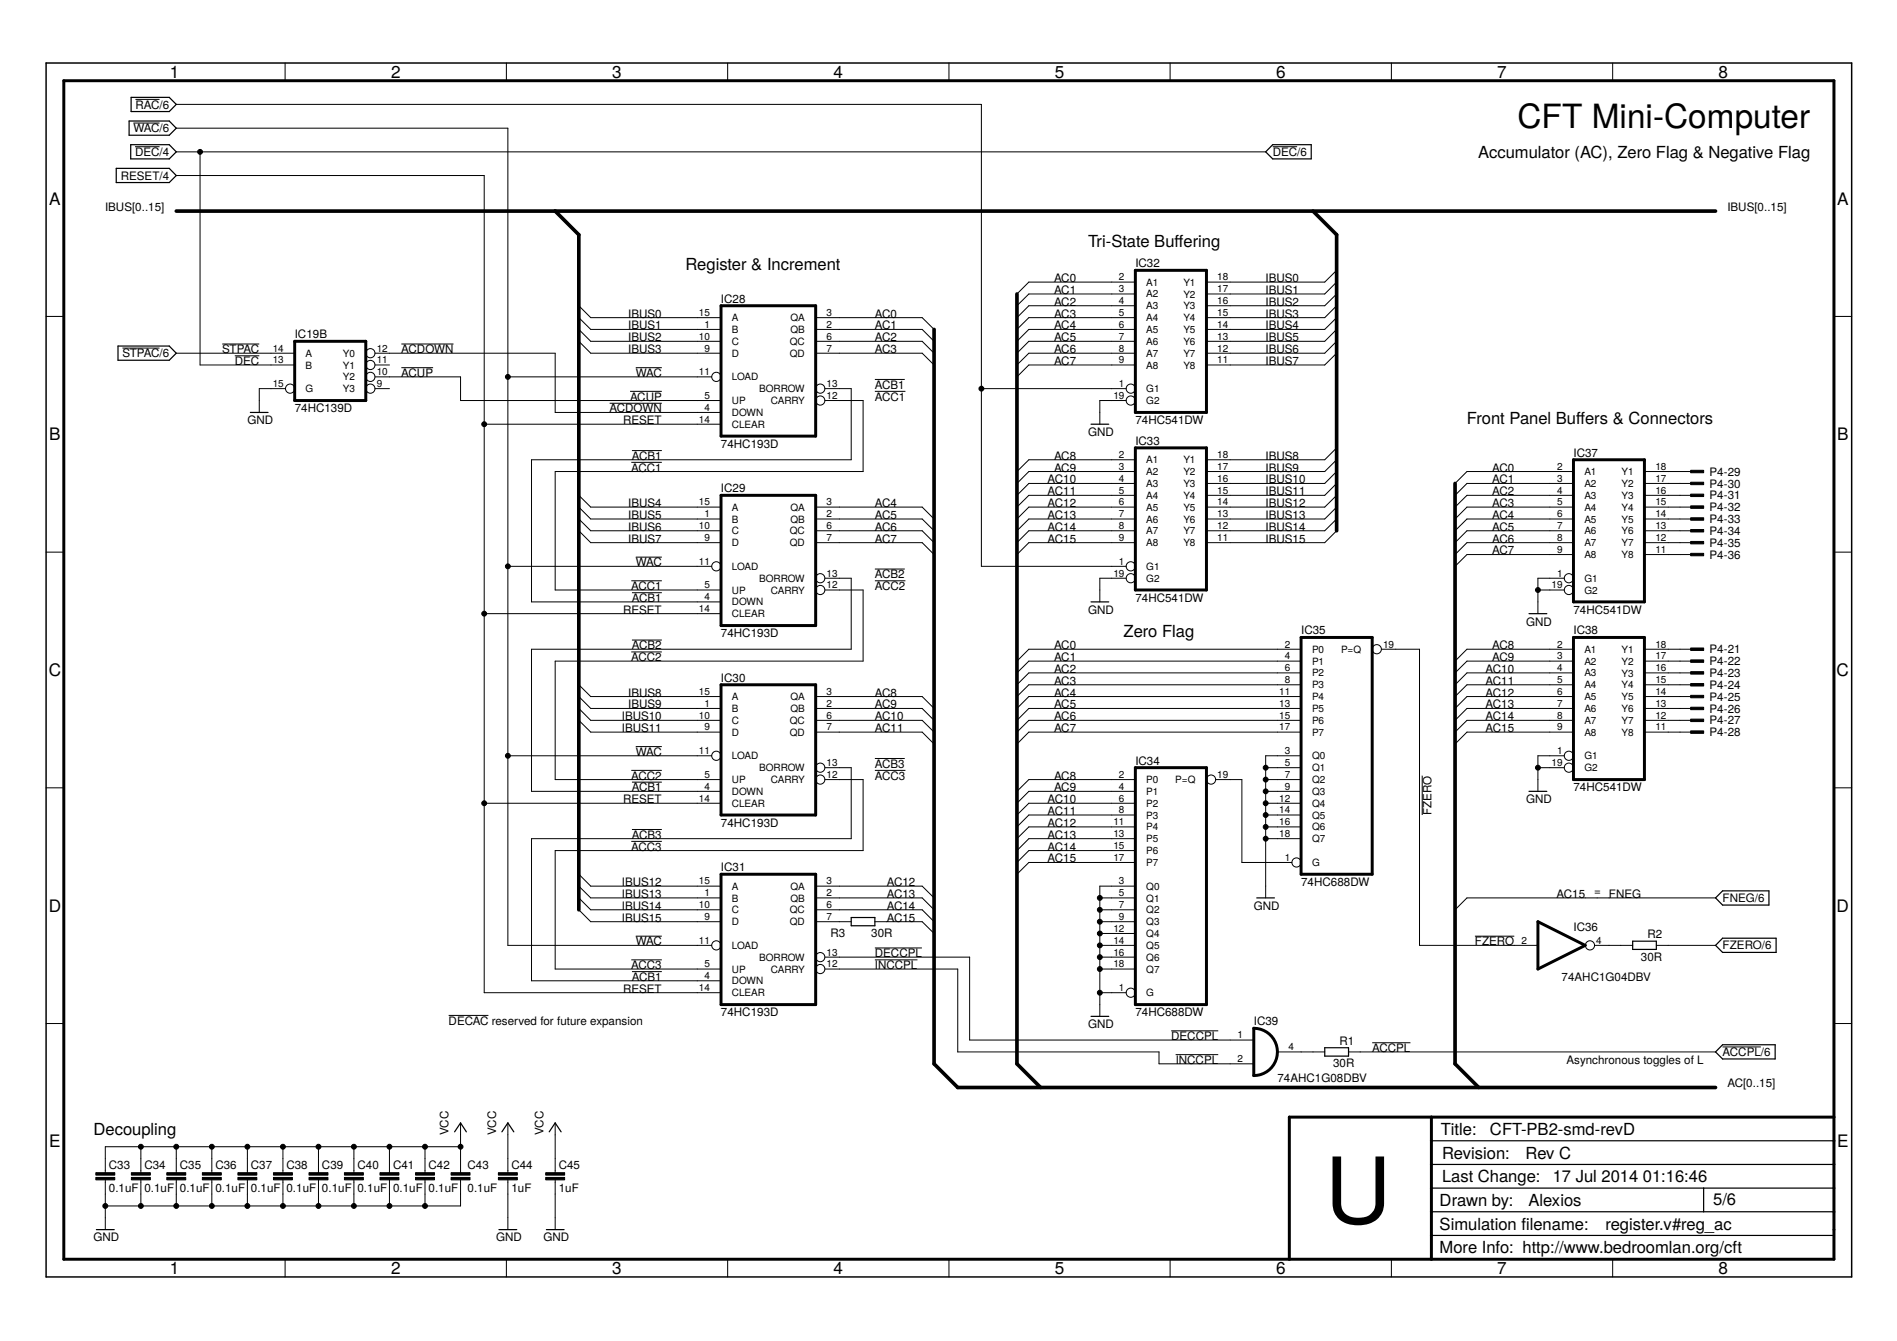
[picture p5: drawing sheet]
<svg xmlns="http://www.w3.org/2000/svg" width="297mm" height="210mm" viewBox="0 0 297 210" stroke-linecap="round" stroke-linejoin="round" font-family="sans-serif">
<defs><g id="words">
<text font-size="14.4" x="207.4" y="191.5">U</text>
<text font-size="5.2" x="237.6" y="20.1">CFT Mini-Computer</text>
<g font-size="2.7">
<text x="26.6" y="12.2">1</text>
<text x="61.2" y="12.2">2</text>
<text x="95.9" y="12.2">3</text>
<text x="130.5" y="12.2">4</text>
<text x="165.2" y="12.2">5</text>
<text x="199.8" y="12.2">6</text>
<text x="234.5" y="12.2">7</text>
<text x="269.1" y="12.2">8</text>
<text x="7.7" y="32">A</text>
<text x="287.7" y="32">A</text>
<text x="7.7" y="68.9">B</text>
<text x="287.7" y="68.9">B</text>
<text x="7.6" y="105.8">C</text>
<text x="287.6" y="105.8">C</text>
<text x="7.6" y="142.7">D</text>
<text x="287.6" y="142.7">D</text>
<text x="7.7" y="179.6">E</text>
<text x="287.7" y="179.6">E</text>
<text x="26.6" y="199.4">1</text>
<text x="61.2" y="199.4">2</text>
<text x="95.9" y="199.4">3</text>
<text x="130.5" y="199.4">4</text>
<text x="165.2" y="199.4">5</text>
<text x="199.8" y="199.4">6</text>
<text x="234.5" y="199.4">7</text>
<text x="269.1" y="199.4">8</text>
</g>
<g font-size="2.6">
<text x="231.4" y="24.7">Accumulator (AC), Zero Flag &amp; Negative Flag</text>
<text x="170.4" y="38.6">Tri-State Bufering</text>
<text x="183.9" y="38.6">f</text>
<text x="107.3" y="42.3">Register &amp; Increment</text>
<text x="229.7" y="66.4">Front Panel Bufers &amp; Connectors</text>
<text x="246.8" y="66.4">f</text>
<text x="175.9" y="99.8">Zero Flag</text>
<text x="14.6" y="177.6">Decoupling</text>
<text x="225.6" y="177.6">Title:</text>
<text x="233.3" y="177.7">CFT-PB2-smd-revD</text>
<text x="225.8" y="181.3">Revision:</text>
<text x="225.8" y="185">Last Change:</text>
<text x="238.9" y="181.4">Rev C</text>
<text x="243.1" y="185">17 Jul 2014</text>
<text x="257.3" y="185">01:16:46</text>
<text x="225.4" y="188.8">Drawn by:</text>
<text x="239.3" y="188.8">Alexios</text>
<text x="268.3" y="188.7">5/6</text>
<text x="225.4" y="192.5">Simulation flename:</text>
<text x="225.4" y="196.2">More Info: http://www.bedroomlan.org/cft</text>
<text x="238.2" y="192.5">i</text>
<text x="251.4" y="192.5">register.v#reg_ac</text>
</g>
<g font-size="1.8">
<text x="21.2" y="17">RAC/6</text>
<text x="20.9" y="20.7">WAC/6</text>
<text x="18.9" y="28.1">RESET/4</text>
<text x="21.1" y="24.4">DEC/4</text>
<text x="199.3" y="24.4">DEC/6</text>
<text x="16.4" y="33">IBUS[0..15]</text>
<text x="270.5" y="33">IBUS[0..15]</text>
<text x="177.8" y="41.8">IC32</text>
<text x="112.9" y="47.4">IC28</text>
<text x="165" y="44.2">AC0</text>
<text x="165" y="46">AC1</text>
<text x="165" y="47.9">AC2</text>
<text x="198.2" y="44.2">IBUS0</text>
<text x="198.2" y="46">IBUS1</text>
<text x="198.2" y="47.9">IBUS2</text>
<text x="46.2" y="53">IC19B</text>
<text x="98.4" y="49.7">IBUS0</text>
<text x="98.4" y="51.6">IBUS1</text>
<text x="98.4" y="53.4">IBUS2</text>
<text x="137" y="49.7">AC0</text>
<text x="137" y="51.6">AC1</text>
<text x="137" y="53.4">AC2</text>
<text x="165" y="49.7">AC3</text>
<text x="165" y="51.6">AC4</text>
<text x="165" y="53.4">AC5</text>
<text x="198.2" y="49.7">IBUS3</text>
<text x="198.2" y="51.6">IBUS4</text>
<text x="198.2" y="53.4">IBUS5</text>
<text x="19.2" y="55.9">STPAC/6</text>
<text x="34.8" y="55.3">STPAC</text>
<text x="36.8" y="57.1">DEC</text>
<text x="62.8" y="55.3">ACDOWN</text>
<text x="62.8" y="59">ACUP</text>
<text x="98.4" y="55.3">IBUS3</text>
<text x="99.5" y="59">WAC</text>
<text x="137" y="55.3">AC3</text>
<text x="165" y="55.3">AC6</text>
<text x="165" y="57.1">AC7</text>
<text x="198.2" y="55.3">IBUS6</text>
<text x="198.2" y="57.1">IBUS7</text>
<text x="46.2" y="64.5">74HC139D</text>
<text x="95.5" y="64.5">ACDOWN</text>
<text x="98.6" y="62.7">ACUP</text>
<text x="137" y="62.7">ACC1</text>
<text x="137" y="60.8">ACB1</text>
<text x="38.7" y="66.4">GND</text>
<text x="97.6" y="66.4">RESET</text>
<text x="98.9" y="72">ACB1</text>
<text x="112.9" y="70.1">74HC193D</text>
<text x="165" y="72">AC8</text>
<text x="170.4" y="68.3">GND</text>
<text x="177.8" y="66.4">74HC541DW</text>
<text x="177.8" y="69.6">IC33</text>
<text x="198.2" y="72">IBUS8</text>
<text x="246.4" y="71.5">IC37</text>
<text x="98.8" y="73.8">ACC1</text>
<text x="112.9" y="77.1">IC29</text>
<text x="164" y="75.7">AC10</text>
<text x="164" y="77.5">AC11</text>
<text x="165" y="73.8">AC9</text>
<text x="198.2" y="73.8">IBUS9</text>
<text x="198.2" y="75.7">IBUS10</text>
<text x="198.2" y="77.5">IBUS11</text>
<text x="233.6" y="73.8">AC0</text>
<text x="233.6" y="75.7">AC1</text>
<text x="233.6" y="77.5">AC2</text>
<text x="267.7" y="74.5">P4-29</text>
<text x="267.7" y="76.3">P4-30</text>
<text x="98.4" y="79.4">IBUS4</text>
<text x="98.4" y="81.2">IBUS5</text>
<text x="98.4" y="83.1">IBUS6</text>
<text x="137" y="79.4">AC4</text>
<text x="137" y="81.2">AC5</text>
<text x="137" y="83.1">AC6</text>
<text x="164" y="79.4">AC12</text>
<text x="164" y="81.2">AC13</text>
<text x="164" y="83.1">AC14</text>
<text x="198.2" y="79.4">IBUS12</text>
<text x="198.2" y="81.2">IBUS13</text>
<text x="198.2" y="83.1">IBUS14</text>
<text x="233.6" y="79.4">AC3</text>
<text x="233.6" y="81.2">AC4</text>
<text x="233.6" y="83.1">AC5</text>
<text x="267.7" y="78.2">P4-31</text>
<text x="267.7" y="80">P4-32</text>
<text x="267.7" y="81.9">P4-33</text>
<text x="267.7" y="83.7">P4-34</text>
<text x="98.4" y="84.9">IBUS7</text>
<text x="99.5" y="88.6">WAC</text>
<text x="137" y="84.9">AC7</text>
<text x="164" y="84.9">AC15</text>
<text x="198.2" y="84.9">IBUS15</text>
<text x="233.6" y="84.9">AC6</text>
<text x="233.6" y="86.8">AC7</text>
<text x="267.7" y="85.6">P4-35</text>
<text x="267.7" y="87.4">P4-36</text>
<text x="98.8" y="92.4">ACC1</text>
<text x="98.9" y="94.2">ACB1</text>
<text x="137" y="92.4">ACC2</text>
<text x="137" y="90.5">ACB2</text>
<text x="177.8" y="94.2">74HC541DW</text>
<text x="97.6" y="96.1">RESET</text>
<text x="98.9" y="101.6">ACB2</text>
<text x="112.9" y="99.8">74HC193D</text>
<text x="165" y="101.6">AC0</text>
<text x="170.4" y="96.1">GND</text>
<text x="203.7" y="99.3">IC35</text>
<text x="233.6" y="101.6">AC8</text>
<text x="239" y="97.9">GND</text>
<text x="246.4" y="96.1">74HC541DW</text>
<text x="246.4" y="99.3">IC38</text>
<text x="98.8" y="103.5">ACC2</text>
<text x="112.9" y="106.7">IC30</text>
<text x="165" y="103.5">AC1</text>
<text x="165" y="105.3">AC2</text>
<text x="165" y="107.2">AC3</text>
<text x="232.6" y="105.3">AC10</text>
<text x="232.6" y="107.2">AC11</text>
<text x="233.6" y="103.5">AC9</text>
<text x="267.7" y="102.3">P4-21</text>
<text x="267.7" y="104.1">P4-22</text>
<text x="267.7" y="106">P4-23</text>
<text x="267.7" y="107.8">P4-24</text>
<text x="97.4" y="112.7">IBUS10</text>
<text x="98.4" y="109">IBUS8</text>
<text x="98.4" y="110.9">IBUS9</text>
<text x="137" y="109">AC8</text>
<text x="137" y="110.9">AC9</text>
<text x="137" y="112.7">AC10</text>
<text x="165" y="109">AC4</text>
<text x="165" y="110.9">AC5</text>
<text x="165" y="112.7">AC6</text>
<text x="232.6" y="109">AC12</text>
<text x="232.6" y="110.9">AC13</text>
<text x="232.6" y="112.7">AC14</text>
<text x="267.7" y="109.7">P4-25</text>
<text x="267.7" y="111.5">P4-26</text>
<text x="267.7" y="113.4">P4-27</text>
<text x="97.4" y="114.6">IBUS11</text>
<text x="99.5" y="118.3">WAC</text>
<text x="137" y="114.6">AC11</text>
<text x="165" y="114.6">AC7</text>
<text x="177.8" y="119.7">IC34</text>
<text x="232.6" y="114.6">AC15</text>
<text x="267.7" y="115.2">P4-28</text>
<text x="97.6" y="125.7">RESET</text>
<text x="98.8" y="122">ACC2</text>
<text x="98.9" y="123.9">ACB1</text>
<text x="137" y="122">ACC3</text>
<text x="137" y="120.2">ACB3</text>
<text x="164" y="125.7">AC10</text>
<text x="165" y="122">AC8</text>
<text x="165" y="123.9">AC9</text>
<text x="239" y="125.7">GND</text>
<text x="246.4" y="123.9">74HC541DW</text>
<text x="98.9" y="131.3">ACB3</text>
<text x="112.9" y="129.4">74HC193D</text>
<text x="164" y="127.6">AC11</text>
<text x="164" y="129.4">AC12</text>
<text x="164" y="131.3">AC13</text>
<text x="224.1" y="127.6" transform="rotate(-90 224.1 127.6)">FZERO</text>
<text x="98.8" y="133.1">ACC3</text>
<text x="112.9" y="136.4">IC31</text>
<text x="164" y="133.1">AC14</text>
<text x="164" y="135">AC15</text>
<text x="97.4" y="138.7">IBUS12</text>
<text x="97.4" y="140.6">IBUS13</text>
<text x="97.4" y="142.4">IBUS14</text>
<text x="138.8" y="138.7">AC12</text>
<text x="138.8" y="140.6">AC13</text>
<text x="138.8" y="142.4">AC14</text>
<text x="196.3" y="142.4">GND</text>
<text x="203.7" y="138.7">74HC688DW</text>
<text x="243.7" y="140.6">AC15</text>
<text x="249.6" y="140.1">=</text>
<text x="251.9" y="140.6">FNEG</text>
<text x="269.7" y="141.2">FNEG/6</text>
<text x="97.4" y="144.3">IBUS15</text>
<text x="99.5" y="148">WAC</text>
<text x="130" y="146.7">R3</text>
<text x="136.4" y="146.7">30R</text>
<text x="137" y="149.8">DECCPL</text>
<text x="138.8" y="144.3">AC15</text>
<text x="230.9" y="148">FZERO</text>
<text x="246.4" y="145.7">IC36</text>
<text x="258" y="146.9">R2</text>
<text x="269.7" y="148.6">FZERO/6</text>
<text x="97.6" y="155.4">RESET</text>
<text x="98.8" y="151.7">ACC3</text>
<text x="98.9" y="153.5">ACB1</text>
<text x="137" y="151.7">INCCPL</text>
<text x="244.5" y="153.5">74AHC1G04DBV</text>
<text x="256.9" y="150.4">30R</text>
<text x="70.3" y="160.4">DECAC reserved for future expansion</text>
<text x="112.9" y="159.1">74HC193D</text>
<text x="170.4" y="160.9">GND</text>
<text x="177.8" y="159.1">74HC688DW</text>
<text x="196.3" y="160.5">IC39</text>
<text x="183.4" y="162.8">DECCPL</text>
<text x="184.1" y="166.5">INCCPL</text>
<text x="208.7" y="167.1">30R</text>
<text x="209.8" y="163.6">R1</text>
<text x="214.9" y="164.7">ACCPL</text>
<text x="245.3" y="166.5">Asynchronous toggles of L</text>
<text x="269.7" y="165.3">ACCPL/6</text>
<text x="200" y="169.3">74AHC1G08DBV</text>
<text x="270.5" y="170.2">AC[0..15]</text>
<text x="70.3" y="177.6" transform="rotate(-90 70.3 177.6)">VCC</text>
<text x="77.7" y="177.6" transform="rotate(-90 77.7 177.6)">VCC</text>
<text x="85.1" y="177.6" transform="rotate(-90 85.1 177.6)">VCC</text>
<text x="17" y="182.9">C33</text>
<text x="22.6" y="182.9">C34</text>
<text x="28.2" y="182.9">C35</text>
<text x="33.7" y="182.9">C36</text>
<text x="39.3" y="182.9">C37</text>
<text x="44.9" y="182.9">C38</text>
<text x="50.4" y="182.9">C39</text>
<text x="56" y="182.9">C40</text>
<text x="61.5" y="182.9">C41</text>
<text x="67.1" y="182.9">C42</text>
<text x="73.2" y="182.9">C43</text>
<text x="80.1" y="182.9">C44</text>
<text x="87.5" y="182.9">C45</text>
<text x="17" y="186.6">0.1uF 0.1uF 0.1uF 0.1uF 0.1uF 0.1uF 0.1uF 0.1uF 0.1uF 0.1uF</text>
<text x="73.2" y="186.6">0.1uF</text>
<text x="80.1" y="186.6">1uF</text>
<text x="87.5" y="186.6">1uF</text>
<text x="14.6" y="194.3">GND</text>
<text x="77.7" y="194.3">GND</text>
<text x="85.1" y="194.3">GND</text>
</g>
<g font-size="1.6">
<text x="175.2" y="43.9">2</text>
<text x="175.2" y="45.8">3</text>
<text x="175.2" y="47.6">4</text>
<text x="179.5" y="44.7">A1</text>
<text x="179.5" y="46.6">A2</text>
<text x="185.3" y="46.6">Y2</text>
<text x="185.3" y="44.7">Y1</text>
<text x="190.6" y="47.6">16</text>
<text x="190.6" y="45.8">17</text>
<text x="190.6" y="43.9">18</text>
<text x="109.5" y="49.5">15</text>
<text x="109.5" y="53.2">10</text>
<text x="110.3" y="51.3">1</text>
<text x="114.6" y="50.3">A</text>
<text x="114.6" y="52.1">B</text>
<text x="114.6" y="54">C</text>
<text x="123.7" y="54">QC</text>
<text x="123.8" y="52.1">QB</text>
<text x="123.8" y="50.3">QA</text>
<text x="129.4" y="53.2">6</text>
<text x="129.4" y="51.3">2</text>
<text x="129.4" y="49.5">3</text>
<text x="175.2" y="49.5">5</text>
<text x="175.2" y="51.3">6</text>
<text x="175.2" y="53.2">7</text>
<text x="179.5" y="48.4">A3</text>
<text x="179.5" y="50.3">A4</text>
<text x="179.5" y="52.1">A5</text>
<text x="179.5" y="54">A6</text>
<text x="185.3" y="54">Y6</text>
<text x="185.3" y="52.1">Y5</text>
<text x="185.3" y="50.3">Y4</text>
<text x="185.3" y="48.4">Y3</text>
<text x="190.6" y="53.2">13</text>
<text x="190.6" y="51.3">14</text>
<text x="190.6" y="49.5">15</text>
<text x="42.7" y="55">14</text>
<text x="42.7" y="56.9">13</text>
<text x="47.9" y="55.8">A</text>
<text x="47.9" y="57.7">B</text>
<text x="53.7" y="55.8">Y0</text>
<text x="53.7" y="57.7">Y1</text>
<text x="53.7" y="59.6">Y2</text>
<text x="59" y="55">12</text>
<text x="59" y="56.9">11</text>
<text x="59" y="58.7">10</text>
<text x="109.5" y="58.7">11</text>
<text x="110.3" y="55">9</text>
<text x="114.6" y="55.8">D</text>
<text x="114.6" y="59.5">LOAD</text>
<text x="123.7" y="55.8">QD</text>
<text x="129.4" y="55">7</text>
<text x="175.2" y="55">8</text>
<text x="175.2" y="56.9">9</text>
<text x="179.5" y="55.8">A7</text>
<text x="179.5" y="57.7">A8</text>
<text x="185.3" y="57.7">Y8</text>
<text x="185.3" y="55.8">Y7</text>
<text x="190.6" y="56.9">11</text>
<text x="190.6" y="55">12</text>
<text x="42.7" y="60.6">15</text>
<text x="47.9" y="61.4">G</text>
<text x="53.7" y="61.4">Y3</text>
<text x="59" y="60.6">9</text>
<text x="110.3" y="62.4">5</text>
<text x="110.3" y="64.3">4</text>
<text x="114.6" y="63.3">UP</text>
<text x="114.6" y="65.1">DOWN</text>
<text x="118.9" y="61.4">BORROW</text>
<text x="120.7" y="63.3">CARRY</text>
<text x="129.4" y="60.6">13</text>
<text x="129.4" y="62.4">12</text>
<text x="174.3" y="62.4">19</text>
<text x="175.2" y="60.6">1</text>
<text x="179.5" y="61.4">G1</text>
<text x="179.5" y="63.3">G2</text>
<text x="109.5" y="66.1">14</text>
<text x="114.6" y="67">CLEAR</text>
<text x="175.2" y="71.7">2</text>
<text x="190.6" y="71.7">18</text>
<text x="175.2" y="73.6">3</text>
<text x="175.2" y="75.4">4</text>
<text x="175.2" y="77.3">5</text>
<text x="179.5" y="72.5">A1</text>
<text x="179.5" y="74.4">A2</text>
<text x="179.5" y="76.2">A3</text>
<text x="185.3" y="76.2">Y3</text>
<text x="185.3" y="74.4">Y2</text>
<text x="185.3" y="72.5">Y1</text>
<text x="190.6" y="77.3">15</text>
<text x="190.6" y="75.4">16</text>
<text x="190.6" y="73.6">17</text>
<text x="243.8" y="73.6">2</text>
<text x="243.8" y="75.4">3</text>
<text x="243.8" y="77.3">4</text>
<text x="248.1" y="74.4">A1</text>
<text x="248.1" y="76.2">A2</text>
<text x="253.9" y="76.2">Y2</text>
<text x="253.9" y="74.4">Y1</text>
<text x="259.2" y="77.3">16</text>
<text x="259.2" y="75.4">17</text>
<text x="259.2" y="73.6">18</text>
<text x="109.5" y="79.1">15</text>
<text x="109.5" y="82.8">10</text>
<text x="110.3" y="81">1</text>
<text x="114.6" y="79.9">A</text>
<text x="114.6" y="81.8">B</text>
<text x="114.6" y="83.6">C</text>
<text x="123.7" y="83.7">QC</text>
<text x="123.8" y="81.8">QB</text>
<text x="123.8" y="79.9">QA</text>
<text x="129.4" y="82.8">6</text>
<text x="129.4" y="81">2</text>
<text x="129.4" y="79.1">3</text>
<text x="175.2" y="79.1">6</text>
<text x="175.2" y="81">7</text>
<text x="175.2" y="82.8">8</text>
<text x="179.5" y="78.1">A4</text>
<text x="179.5" y="79.9">A5</text>
<text x="179.5" y="81.8">A6</text>
<text x="179.5" y="83.6">A7</text>
<text x="185.3" y="83.7">Y7</text>
<text x="185.3" y="81.8">Y6</text>
<text x="185.3" y="79.9">Y5</text>
<text x="185.3" y="78.1">Y4</text>
<text x="190.6" y="82.8">12</text>
<text x="190.6" y="81">13</text>
<text x="190.6" y="79.1">14</text>
<text x="243.8" y="79.1">5</text>
<text x="243.8" y="81">6</text>
<text x="243.8" y="82.8">7</text>
<text x="248.1" y="78.1">A3</text>
<text x="248.1" y="79.9">A4</text>
<text x="248.1" y="81.8">A5</text>
<text x="248.1" y="83.6">A6</text>
<text x="253.9" y="83.7">Y6</text>
<text x="253.9" y="81.8">Y5</text>
<text x="253.9" y="79.9">Y4</text>
<text x="253.9" y="78.1">Y3</text>
<text x="259.2" y="82.8">13</text>
<text x="259.2" y="81">14</text>
<text x="259.2" y="79.1">15</text>
<text x="109.5" y="88.4">11</text>
<text x="110.3" y="84.7">9</text>
<text x="114.6" y="85.5">D</text>
<text x="114.6" y="89.2">LOAD</text>
<text x="123.7" y="85.5">QD</text>
<text x="129.4" y="84.7">7</text>
<text x="175.2" y="88.4">1</text>
<text x="175.2" y="84.7">9</text>
<text x="179.5" y="89.2">G1</text>
<text x="179.5" y="85.5">A8</text>
<text x="185.3" y="85.5">Y8</text>
<text x="190.6" y="84.7">11</text>
<text x="243.8" y="84.7">8</text>
<text x="243.8" y="86.5">9</text>
<text x="248.1" y="85.5">A7</text>
<text x="248.1" y="87.4">A8</text>
<text x="253.9" y="87.4">Y8</text>
<text x="253.9" y="85.5">Y7</text>
<text x="259.2" y="86.5">11</text>
<text x="259.2" y="84.7">12</text>
<text x="109.5" y="95.8">14</text>
<text x="110.3" y="92.1">5</text>
<text x="110.3" y="93.9">4</text>
<text x="114.6" y="92.9">UP</text>
<text x="114.6" y="94.8">DOWN</text>
<text x="118.9" y="91.1">BORROW</text>
<text x="120.7" y="92.9">CARRY</text>
<text x="129.4" y="90.2">13</text>
<text x="129.4" y="92.1">12</text>
<text x="174.3" y="90.2">19</text>
<text x="179.5" y="91.1">G2</text>
<text x="242.9" y="92.1">19</text>
<text x="243.8" y="90.2">1</text>
<text x="248.1" y="91.1">G1</text>
<text x="248.1" y="92.9">G2</text>
<text x="114.6" y="96.6">CLEAR</text>
<text x="201.2" y="101.4">2</text>
<text x="216.6" y="101.4">19</text>
<text x="243.8" y="101.4">2</text>
<text x="259.2" y="101.4">18</text>
<text x="201.2" y="103.2">4</text>
<text x="201.2" y="105.1">6</text>
<text x="201.2" y="106.9">8</text>
<text x="205.4" y="102.2">P0</text>
<text x="205.4" y="104">P1</text>
<text x="205.4" y="105.9">P2</text>
<text x="205.4" y="107.7">P3</text>
<text x="210" y="102.2">P=Q</text>
<text x="243.8" y="103.2">3</text>
<text x="243.8" y="105.1">4</text>
<text x="243.8" y="106.9">5</text>
<text x="248.1" y="102.2">A1</text>
<text x="248.1" y="104">A2</text>
<text x="248.1" y="105.9">A3</text>
<text x="248.1" y="107.7">A4</text>
<text x="253.9" y="107.8">Y4</text>
<text x="253.9" y="105.9">Y3</text>
<text x="253.9" y="104">Y2</text>
<text x="253.9" y="102.2">Y1</text>
<text x="259.2" y="106.9">15</text>
<text x="259.2" y="105.1">16</text>
<text x="259.2" y="103.2">17</text>
<text x="109.5" y="108.8">15</text>
<text x="109.5" y="112.5">10</text>
<text x="110.3" y="110.6">1</text>
<text x="114.6" y="109.6">A</text>
<text x="114.6" y="111.4">B</text>
<text x="114.6" y="113.3">C</text>
<text x="123.7" y="113.3">QC</text>
<text x="123.8" y="111.5">QB</text>
<text x="123.8" y="109.6">QA</text>
<text x="129.4" y="112.5">6</text>
<text x="129.4" y="110.6">2</text>
<text x="129.4" y="108.8">3</text>
<text x="200.3" y="108.8">11</text>
<text x="200.3" y="110.6">13</text>
<text x="200.3" y="112.5">15</text>
<text x="205.4" y="109.6">P4</text>
<text x="205.4" y="111.4">P5</text>
<text x="205.4" y="113.3">P6</text>
<text x="243.8" y="108.8">6</text>
<text x="243.8" y="110.6">7</text>
<text x="243.8" y="112.5">8</text>
<text x="248.1" y="109.6">A5</text>
<text x="248.1" y="111.4">A6</text>
<text x="248.1" y="113.3">A7</text>
<text x="253.9" y="113.3">Y7</text>
<text x="253.9" y="111.5">Y6</text>
<text x="253.9" y="109.6">Y5</text>
<text x="259.2" y="112.5">12</text>
<text x="259.2" y="110.6">13</text>
<text x="259.2" y="108.8">14</text>
<text x="109.5" y="118">11</text>
<text x="110.3" y="114.3">9</text>
<text x="114.6" y="115.2">D</text>
<text x="114.6" y="118.9">LOAD</text>
<text x="123.7" y="115.2">QD</text>
<text x="129.4" y="114.3">7</text>
<text x="129.4" y="119.9">13</text>
<text x="200.3" y="114.3">17</text>
<text x="201.2" y="118">3</text>
<text x="201.2" y="119.9">5</text>
<text x="205.4" y="118.9">Q0</text>
<text x="205.4" y="115.2">P7</text>
<text x="242.9" y="119.9">19</text>
<text x="243.8" y="118">1</text>
<text x="243.8" y="114.3">9</text>
<text x="248.1" y="118.9">G1</text>
<text x="248.1" y="115.2">A8</text>
<text x="253.9" y="115.2">Y8</text>
<text x="259.2" y="114.3">11</text>
<text x="109.5" y="125.5">14</text>
<text x="110.3" y="121.8">5</text>
<text x="110.3" y="123.6">4</text>
<text x="114.6" y="122.6">UP</text>
<text x="114.6" y="124.4">DOWN</text>
<text x="118.9" y="120.7">BORROW</text>
<text x="120.7" y="122.6">CARRY</text>
<text x="129.4" y="121.8">12</text>
<text x="175.2" y="121.8">2</text>
<text x="175.2" y="123.6">4</text>
<text x="175.2" y="125.5">6</text>
<text x="179.5" y="122.6">P0</text>
<text x="179.5" y="124.4">P1</text>
<text x="184" y="122.6">P=Q</text>
<text x="190.6" y="121.8">19</text>
<text x="200.3" y="125.5">12</text>
<text x="201.2" y="121.8">7</text>
<text x="201.2" y="123.6">9</text>
<text x="205.4" y="120.7">Q1</text>
<text x="205.4" y="122.6">Q2</text>
<text x="205.4" y="124.4">Q3</text>
<text x="248.1" y="120.7">G2</text>
<text x="114.6" y="126.3">CLEAR</text>
<text x="174.3" y="129.2">11</text>
<text x="174.3" y="131">13</text>
<text x="175.2" y="127.3">8</text>
<text x="179.5" y="126.3">P2</text>
<text x="179.5" y="128.1">P3</text>
<text x="179.5" y="130">P4</text>
<text x="179.5" y="131.8">P5</text>
<text x="200.3" y="127.3">14</text>
<text x="200.3" y="129.2">16</text>
<text x="200.3" y="131">18</text>
<text x="205.4" y="126.3">Q4</text>
<text x="205.4" y="128.1">Q5</text>
<text x="205.4" y="130">Q6</text>
<text x="205.4" y="131.8">Q7</text>
<text x="174.3" y="132.9">15</text>
<text x="174.3" y="134.7">17</text>
<text x="179.5" y="133.7">P6</text>
<text x="179.5" y="135.5">P7</text>
<text x="201.2" y="134.7">1</text>
<text x="205.4" y="135.5">G</text>
<text x="109.5" y="138.4">15</text>
<text x="109.5" y="142.1">10</text>
<text x="110.3" y="140.3">1</text>
<text x="114.6" y="139.3">A</text>
<text x="114.6" y="141.1">B</text>
<text x="114.6" y="143">C</text>
<text x="123.7" y="143">QC</text>
<text x="123.8" y="141.1">QB</text>
<text x="123.8" y="139.3">QA</text>
<text x="129.4" y="142.1">6</text>
<text x="129.4" y="140.3">2</text>
<text x="129.4" y="138.4">3</text>
<text x="175.2" y="138.4">3</text>
<text x="175.2" y="140.3">5</text>
<text x="175.2" y="142.1">7</text>
<text x="179.5" y="139.3">Q0</text>
<text x="179.5" y="141.1">Q1</text>
<text x="179.5" y="143">Q2</text>
<text x="109.5" y="147.7">11</text>
<text x="110.3" y="144">9</text>
<text x="114.6" y="144.8">D</text>
<text x="114.6" y="148.5">LOAD</text>
<text x="123.7" y="144.8">QD</text>
<text x="129.4" y="144">7</text>
<text x="129.4" y="149.6">13</text>
<text x="174.3" y="145.9">12</text>
<text x="174.3" y="147.7">14</text>
<text x="174.3" y="149.6">16</text>
<text x="175.2" y="144">9</text>
<text x="179.5" y="144.8">Q3</text>
<text x="179.5" y="146.7">Q4</text>
<text x="179.5" y="148.5">Q5</text>
<text x="238.2" y="147.7">2</text>
<text x="249.9" y="147.7">4</text>
<text x="109.5" y="155.1">14</text>
<text x="110.3" y="151.4">5</text>
<text x="110.3" y="153.3">4</text>
<text x="114.6" y="152.2">UP</text>
<text x="114.6" y="154.1">DOWN</text>
<text x="114.6" y="155.9">CLEAR</text>
<text x="118.9" y="150.4">BORROW</text>
<text x="120.7" y="152.2">CARRY</text>
<text x="129.4" y="151.4">12</text>
<text x="174.3" y="151.4">18</text>
<text x="175.2" y="155.1">1</text>
<text x="179.5" y="155.9">G</text>
<text x="179.5" y="150.4">Q6</text>
<text x="179.5" y="152.2">Q7</text>
<text x="193.7" y="162.5">1</text>
<text x="193.7" y="166.2">2</text>
<text x="201.7" y="164.4">4</text>
</g>
</g></defs>
<g fill="none" stroke="#000" stroke-width=".16">
<path d="M10 12.6h277.2v184.5h-277.2zM20.9 19.3h4.1M21.2 15.6h3.8M27.6 16.3h126.1v72.3h22.6M44.6 9.9v2.7M79.3 9.9v2.7M113.9 9.9v2.7M148.6 9.9v2.7M183.2 9.9v2.7M217.9 9.9v2.7M252.5 9.9v2.7M21.1 23h3.9"/>
<path d="M27.6 20.1h51.9v127.9h31.9M27.6 27.5h48.2v127.9h37.1M27.6 23.8h170.6M31.3 23.8v33.3h14.8M199.3 23h3.8M7.2 49.5h2.8M19.2 54.5h5.8M27.6 55.3h18.5M34.8 53.8h5.8M36.8 55.7h3.8M58.7 59h13.4v3.7h40.8M58.7 55.3h28.2v9.3h26"/>
<path d="M58.7 57.1h2.3M62.8 57.6h5M62.8 53.8h8.2M79.5 59h31.9M90.6 47.9l1.9 1.8h20.4M90.6 49.7l1.9 1.9h20.4M90.6 51.6l1.9 1.8h20.4M90.6 53.4l1.9 1.9h20.4M99.5 57.6h4.1M127.7 49.7h16.7l1.9 1.9M127.7 51.6h16.7l1.9 1.8M127.7 53.4h16.7l1.9 1.9"/>
<path d="M127.7 55.3h16.7l1.9 1.8M137 59.4h4.7M177.8 49.7h-16.7l-1.9 1.9M177.8 51.6h-16.7l-1.9 1.8M177.8 53.4h-16.7l-1.9 1.9M177.8 55.3h-16.7l-1.9 1.8M177.8 44.2h-16.7l-1.9 1.8M177.8 46h-16.7l-1.9 1.9M177.8 47.9h-16.7l-1.9 1.8M177.8 57.1h-16.7l-1.9 1.9M209.3 47.9l-1.9 1.8h-18.5M209.3 49.7l-1.9 1.9h-18.5"/>
<path d="M209.3 51.6l-1.9 1.8h-18.5M209.3 53.4l-1.9 1.9h-18.5M209.3 42.3l-1.9 1.9h-18.5M209.3 44.2l-1.9 1.8h-18.5M209.3 46l-1.9 1.9h-18.5M209.3 55.3l-1.9 1.8h-18.5M287.2 49.5h2.7M44.7 60.8h-4.1v3.8M58.7 60.8h2.3M75.8 66.4h37.1M90.6 77.5l1.9 1.9h20.4M90.6 79.4l1.9 1.8h20.4"/>
<path d="M95.5 63.1h8.1M98.7 61.3h4.9M98.8 72.4h4.8M99 70.5h4.6M127.7 79.4h16.7l1.9 1.8M129.2 62.7h5.9v11.1h-48.2v18.6h26M129.2 60.8h4.1v11.2h-50.1v22.2h29.7M137 61.3h4.8M153.7 60.8h22.6M176.3 62.7h-4.1v3.7M177.8 79.4h-16.7l-1.9 1.8M177.8 72h-16.7l-1.9 1.8"/>
<path d="M177.8 73.8h-16.7l-1.9 1.9M177.8 75.7h-16.7l-1.9 1.8M177.8 77.5h-16.7l-1.9 1.9M209.3 77.5l-1.9 1.9h-18.5M209.3 79.4l-1.9 1.8h-18.5M209.3 70.1l-1.9 1.9h-18.5M209.3 72l-1.9 1.8h-18.5M209.3 73.8l-1.9 1.9h-18.5M209.3 75.7l-1.9 1.8h-18.5M246.4 79.4h-16.7l-1.9 1.8M246.4 73.8h-16.7l-1.9 1.9M246.4 75.7h-16.7l-1.9 1.8"/>
<path d="M246.4 77.5h-16.7l-1.9 1.9M257.5 79.4h7.4M257.5 73.8h7.4M257.5 75.7h7.4M257.5 77.5h7.4M7.2 86.4h2.8M75.8 96.1h37.1M79.5 88.6h31.9M90.6 81.2l1.9 1.9h20.4M90.6 83.1l1.9 1.8h20.4M98.8 90.9h4.8M99 92.8h4.6"/>
<path d="M99.5 87.2h4.1M127.7 81.2h16.7l1.9 1.9M127.7 83.1h16.7l1.9 1.8M127.7 84.9h16.7l1.9 1.9M129.2 92.4h5.9v11.1h-48.2v18.5h26M129.2 90.5h4.1v11.1h-50.1v22.3h29.7M137 90.9h4.8M137 89.1h4.7M176.3 90.5h-4.1v3.7M177.8 81.2h-16.7l-1.9 1.9M177.8 83.1h-16.7l-1.9 1.8M177.8 84.9h-16.7l-1.9 1.9"/>
<path d="M209.3 81.2l-1.9 1.9h-18.5M209.3 83.1l-1.9 1.8h-18.5M240.8 92.4h4.1M244.9 90.5h-4.1v5.6M246.4 81.2h-16.7l-1.9 1.9M246.4 83.1h-16.7l-1.9 1.8M246.4 84.9h-16.7l-1.9 1.9M246.4 86.8h-16.7l-1.9 1.8M257.5 81.2h7.4M257.5 83.1h7.4M257.5 84.9h7.4M257.5 86.8h7.4"/>
<path d="M287.2 86.4h2.7M79.5 118.3h31.9M90.6 107.2l1.9 1.8h20.4M90.6 109l1.9 1.9h20.4M90.6 110.9l1.9 1.9h20.4M90.6 112.8l1.9 1.8h20.4M98.8 102h4.8M99 100.2h4.6M99.5 116.9h4.1M127.7 109h16.7l1.9 1.9M127.7 110.9h16.7l1.9 1.9M127.7 112.8h16.7l1.9 1.8"/>
<path d="M127.7 114.6h16.7l1.9 1.9M137 118.7h4.7M203.7 109h-42.6l-1.9 1.9M203.7 110.9h-42.6l-1.9 1.9M203.7 112.8h-42.6l-1.9 1.8M203.7 114.6h-42.6l-1.9 1.9M203.7 118.3h-5.5v22.2M203.7 101.6h-42.6l-1.9 1.9M203.7 103.5h-42.6l-1.9 1.8M203.7 105.3h-42.6l-1.9 1.9M203.7 107.2h-42.6l-1.9 1.8M216.3 101.6h6v46.4h18.5"/>
<path d="M244.9 118.3h-4.1v5.6M246.4 109h-16.7l-1.9 1.9M246.4 110.9h-16.7l-1.9 1.9M246.4 112.8h-16.7l-1.9 1.8M246.4 114.6h-16.7l-1.9 1.9M246.4 101.6h-16.7l-1.9 1.9M246.4 103.5h-16.7l-1.9 1.8M246.4 105.3h-16.7l-1.9 1.9M246.4 107.2h-16.7l-1.9 1.8M257.5 109h7.4M257.5 110.9h7.4M257.5 112.8h7.4"/>
<path d="M257.5 114.6h7.4M257.5 101.6h7.4M257.5 103.5h7.4M257.5 105.3h7.4M257.5 107.2h7.4M7.2 123.3h2.8M75.8 125.7h37.1M90.6 136.8l1.9 1.9h20.4M90.6 138.7l1.9 1.8h20.4M98.8 120.6h4.8M98.8 131.7h4.8M99 122.4h4.6"/>
<path d="M99 129.8h4.6M127.7 138.7h16.7l1.9 1.8M129.2 122h5.9v11.1h-48.2v18.6h26M129.2 120.2h4.1v11.1h-50.1v22.2h29.7M137 120.6h4.8M177.8 122h-16.7l-1.9 1.9M177.8 123.9h-16.7l-1.9 1.8M177.8 125.7h-16.7l-1.9 1.9M177.8 138.7h-5.6v20.4M177.8 127.6h-16.7l-1.9 1.8M177.8 129.4h-16.7l-1.9 1.9M177.8 131.3h-16.7l-1.9 1.8"/>
<path d="M177.8 133.1h-16.7l-1.9 1.9M177.8 135h-16.7l-1.9 1.8M190.4 122h4.1v13h7.8M198.2 122h5.5M198.2 120.2h5.5M198.2 123.9h5.5M198.2 125.7h5.5M198.2 127.6h5.5M198.2 129.4h5.5M198.2 131.3h5.5M222.7 121.4v6.2M240.8 120.2h4.1"/>
<path d="M287.2 123.3h2.7M70.3 158.9h6.2M90.6 140.5l1.9 1.9h20.4M90.6 142.4l1.9 1.9h20.4M98.8 150.2h4.8M99 152.1h4.6M99.5 146.5h4.1M127.7 140.5h16.7l1.9 1.9M127.7 142.4h16.7l1.9 1.9M127.7 144.3h5.6M129.2 151.7h20.8v13h31.5v1.8h14.8M129.2 149.8h22.6v13h44.5"/>
<path d="M137 150.2h6.7M137 148.4h7.4M137 144.3h7.4l1.9 1.8M172.2 151.7h5.6M172.2 140.5h5.6M172.2 142.4h5.6M172.2 144.3h5.6M172.2 148h5.6M172.2 149.8h5.6M172.2 155.4h4.1M172.2 146.1h5.6M230.9 146.5h6.2"/>
<path d="M249.7 148h6M259.4 148h9.2M268.6 140.5h-38.9l-1.9 1.9M7.2 160.2h2.8M22.1 179.5v4.1M27.6 179.5v4.1M33.2 179.5v4.1M38.7 179.5v4.1M44.3 179.5v4.1M49.9 179.5v4.1M55.4 179.5v4.1M61 179.5v4.1"/>
<path d="M66.5 179.5v4.1M72.1 179.5h-55.6v4.1M72.1 175.8v7.8M79.5 175.8v7.8M86.9 175.8v7.8M183.4 161.4h7.4M184.1 165.1h6.7M200 164.7h7.4M211.2 164.7h57.4M214.9 163.2h6M269.7 163.9h6M287.2 160.2h2.7"/>
<path d="M16.5 184.7v7.8M22.1 184.7v4.1M27.6 184.7v4.1M33.2 184.7v4.1M38.7 184.7v4.1M44.3 184.7v4.1M44.6 197.1v2.8M49.9 184.7v4.1M55.4 184.7v4.1M61 184.7v4.1M66.5 184.7v4.1M72.1 184.7v4.1h-55.6"/>
<path d="M79.3 197.1v2.8M79.5 184.7v7.8M86.9 184.7v7.8M113.9 197.1v2.8M148.6 197.1v2.8M183.2 197.1v2.8M217.9 197.1v2.8M252.5 197.1v2.8M287.2 197h.1"/>
<circle cx="58" cy="57.1" r=".72"/>
<circle cx="58" cy="55.3" r=".72"/>
<circle cx="58" cy="59" r=".72"/>
<circle cx="112.2" cy="59" r=".72"/>
<circle cx="45.4" cy="60.8" r=".72"/>
<circle cx="58" cy="60.8" r=".72"/>
<circle cx="128.4" cy="62.7" r=".72"/>
<circle cx="128.4" cy="60.8" r=".72"/>
<circle cx="177.1" cy="62.7" r=".72"/>
<circle cx="177.1" cy="60.8" r=".72"/>
<circle cx="112.2" cy="88.6" r=".72"/>
<circle cx="128.4" cy="90.5" r=".72"/>
<circle cx="128.4" cy="92.4" r=".72"/>
<circle cx="177.1" cy="88.6" r=".72"/>
<circle cx="177.1" cy="90.5" r=".72"/>
<circle cx="245.7" cy="90.5" r=".72"/>
<circle cx="245.7" cy="92.4" r=".72"/>
<circle cx="112.2" cy="118.3" r=".72"/>
<circle cx="215.6" cy="101.6" r=".72"/>
<circle cx="245.7" cy="118.3" r=".72"/>
<circle cx="128.4" cy="120.2" r=".72"/>
<circle cx="128.4" cy="122" r=".72"/>
<circle cx="189.6" cy="122" r=".72"/>
<circle cx="203" cy="135" r=".72"/>
<circle cx="245.7" cy="120.2" r=".72"/>
<circle cx="112.2" cy="148" r=".72"/>
<circle cx="128.4" cy="149.8" r=".72"/>
<circle cx="128.4" cy="151.7" r=".72"/>
<circle cx="177.1" cy="155.4" r=".72"/>
<circle cx="249" cy="148" r=".72"/>
</g>
<g fill="none" stroke="#000" stroke-width=".19">
<path d="M20.2 18.9h6.3l1.1 1.2-1.1 1.1h-6.3zM20.5 15.2h6l1.1 1.1-1.1 1.2h-6zM18.2 26.4h8.3l1.1 1.1-1.1 1.1h-8.3zM20.5 22.6h6l1.1 1.2-1.1 1.1h-6zM199.3 22.6h6v2.3h-6l-1.1-1.1zM18.5 54.2h8l1.1 1.1-1.1 1.1h-8zM39.2 64.6h2.8M170.8 66.4h2.8M170.8 94.2h2.8M239.4 96.1h2.8M239.4 123.9h2.8M269.7 139.4h7.3v2.3h-7.3l-1.1-1.2z"/>
<path d="M133.3 143.6h3.7v1.3h-3.7zM170.8 159.1h2.8M196.8 140.5h2.8M255.7 147.3h3.7v1.3h-3.7zM269.7 146.9h8.4v2.2h-8.4l-1.1-1.1zM71.2 177.2l.9-1.4 .9 1.4M78.6 177.2l.9-1.4 1 1.4M86 177.2l.9-1.4 1 1.4M207.4 164h3.8v1.3h-3.8zM224.1 178.6h63.1M269.7 163.5h8.3v2.3h-8.3l-1.1-1.1zM15.1 192.5h2.8"/>
<path d="M78.1 192.5h2.8M85.6 192.5h2.7M224.1 182.3h63.1M224.1 186h63.1M224.1 189.7h63.1M266.8 186v3.7M287.2 192.5v.9h-63.1"/>
</g>
<g fill="none" stroke="#000" stroke-width=".47">
<path d="M10 12.6h277.2v184.5h-277.2zM46.1 53.4h11.2v9.3h-11.2zM112.9 47.9h14.8v20.4h-14.8zM177.8 42.3h11.1v22.3h-11.1zM112.9 77.5h14.8v20.4h-14.8zM177.8 70.1h11.1v22.3h-11.1zM246.4 72h11.1v22.2h-11.1zM203.7 99.8h11.2v37h-11.2zM246.4 99.8h11.1v22.2h-11.1zM112.9 107.2h14.8v20.4h-14.8zM112.9 136.8h14.8v20.4h-14.8zM177.8 120.2h11.1v37h-11.1z"/>
<path d="M240.8 144.3l7.4 3.7-7.4 3.7zM196.3 161a3.7 3.7 0 0 1 3.7 3.7 3.7 3.7 0 0 1-3.7 3.7zM224.1 174.9v22.2M287.2 174.9h-85.3v22.2"/>
</g>
<path d="M7.2 9.9h282.7v190h-282.7z" fill="none" stroke="#000" stroke-width=".23"/>
<g fill="#000" stroke="#000" stroke-width=".16">
<path d="M264.7 73.6h2.1v.4h-2.1zM264.7 75.5h2.1v.4h-2.1zM264.7 77.3h2.1v.4h-2.1zM264.7 79.2h2.1v.4h-2.1zM264.7 81h2.1v.4h-2.1zM264.7 82.9h2.1v.4h-2.1zM264.7 84.8h2.1v.3h-2.1zM264.7 86.6h2.1v.4h-2.1zM264.7 101.4h2.1v.4h-2.1zM264.7 103.3h2.1v.4h-2.1zM264.7 105.1h2.1v.4h-2.1zM264.7 107h2.1v.4h-2.1z"/>
<path d="M264.7 108.8h2.1v.4h-2.1zM264.7 110.7h2.1v.4h-2.1zM264.7 112.6h2.1v.3h-2.1zM264.7 114.4h2.1v.4h-2.1zM15 183.6h3v.3h-3zM15 184.3h3v.4h-3zM20.6 183.6h2.9v.3h-2.9zM20.6 184.3h2.9v.4h-2.9zM26.1 183.6h3v.3h-3zM26.1 184.3h3v.4h-3zM31.7 183.6h2.9v.3h-2.9zM31.7 184.3h2.9v.4h-2.9z"/>
<path d="M37.3 183.6h2.9v.3h-2.9zM37.3 184.3h2.9v.4h-2.9zM42.8 183.6h3v.3h-3zM42.8 184.3h3v.4h-3zM48.4 183.6h3v.3h-3zM48.4 184.3h3v.4h-3zM53.9 183.6h3v.3h-3zM53.9 184.3h3v.4h-3zM59.5 183.6h3v.3h-3zM59.5 184.3h3v.4h-3zM65.1 183.6h2.9v.3h-2.9zM65.1 184.3h2.9v.4h-2.9z"/>
<path d="M70.6 184.3h3v.4h-3zM70.6 183.6h3v.3h-3zM78 183.6h3v.3h-3zM78 184.3h3v.4h-3zM85.4 183.6h3v.3h-3zM85.4 184.3h3v.4h-3z"/>
</g>
<path d="M27.6 33h241M86.9 33l3.7 3.7v105.7M205.6 33l3.7 3.7v46.4M146.3 51.6v114.9l3.7 3.7h118.6M159.2 46v120.5l3.7 3.7M227.8 75.7v90.8l3.7 3.7" fill="none" stroke="#000" stroke-width=".57"/>
<g fill="#000" stroke="#000" stroke-width=".16">
<circle cx="31.3" cy="23.8" r=".38"/>
<circle cx="79.5" cy="59" r=".38"/>
<circle cx="75.8" cy="66.4" r=".38"/>
<circle cx="153.7" cy="60.8" r=".38"/>
<circle cx="75.8" cy="96.1" r=".38"/>
<circle cx="79.5" cy="88.6" r=".38"/>
<circle cx="240.8" cy="92.4" r=".38"/>
<circle cx="79.5" cy="118.3" r=".38"/>
<circle cx="75.8" cy="125.7" r=".38"/>
<circle cx="198.2" cy="125.7" r=".38"/>
<circle cx="198.2" cy="131.3" r=".38"/>
<circle cx="198.2" cy="122" r=".38"/>
<circle cx="198.2" cy="120.2" r=".38"/>
<circle cx="198.2" cy="127.6" r=".38"/>
<circle cx="198.2" cy="129.4" r=".38"/>
<circle cx="198.2" cy="123.9" r=".38"/>
<circle cx="240.8" cy="120.2" r=".38"/>
<circle cx="172.2" cy="151.7" r=".38"/>
<circle cx="172.2" cy="149.8" r=".38"/>
<circle cx="172.2" cy="148" r=".38"/>
<circle cx="172.2" cy="140.5" r=".38"/>
<circle cx="172.2" cy="142.4" r=".38"/>
<circle cx="172.2" cy="144.3" r=".38"/>
<circle cx="172.2" cy="146.1" r=".38"/>
<circle cx="172.2" cy="155.4" r=".38"/>
<circle cx="22.1" cy="179.5" r=".38"/>
<circle cx="27.6" cy="179.5" r=".38"/>
<circle cx="33.2" cy="179.5" r=".38"/>
<circle cx="38.7" cy="179.5" r=".38"/>
<circle cx="44.3" cy="179.5" r=".38"/>
<circle cx="49.9" cy="179.5" r=".38"/>
<circle cx="55.4" cy="179.5" r=".38"/>
<circle cx="61" cy="179.5" r=".38"/>
<circle cx="66.5" cy="179.5" r=".38"/>
<circle cx="72.1" cy="179.5" r=".38"/>
<circle cx="16.5" cy="188.8" r=".38"/>
<circle cx="22.1" cy="188.8" r=".38"/>
<circle cx="27.6" cy="188.8" r=".38"/>
<circle cx="33.2" cy="188.8" r=".38"/>
<circle cx="38.7" cy="188.8" r=".38"/>
<circle cx="44.3" cy="188.8" r=".38"/>
<circle cx="49.9" cy="188.8" r=".38"/>
<circle cx="55.4" cy="188.8" r=".38"/>
<circle cx="61" cy="188.8" r=".38"/>
<circle cx="66.5" cy="188.8" r=".38"/>
</g>
<use href="#words"/>
</svg>
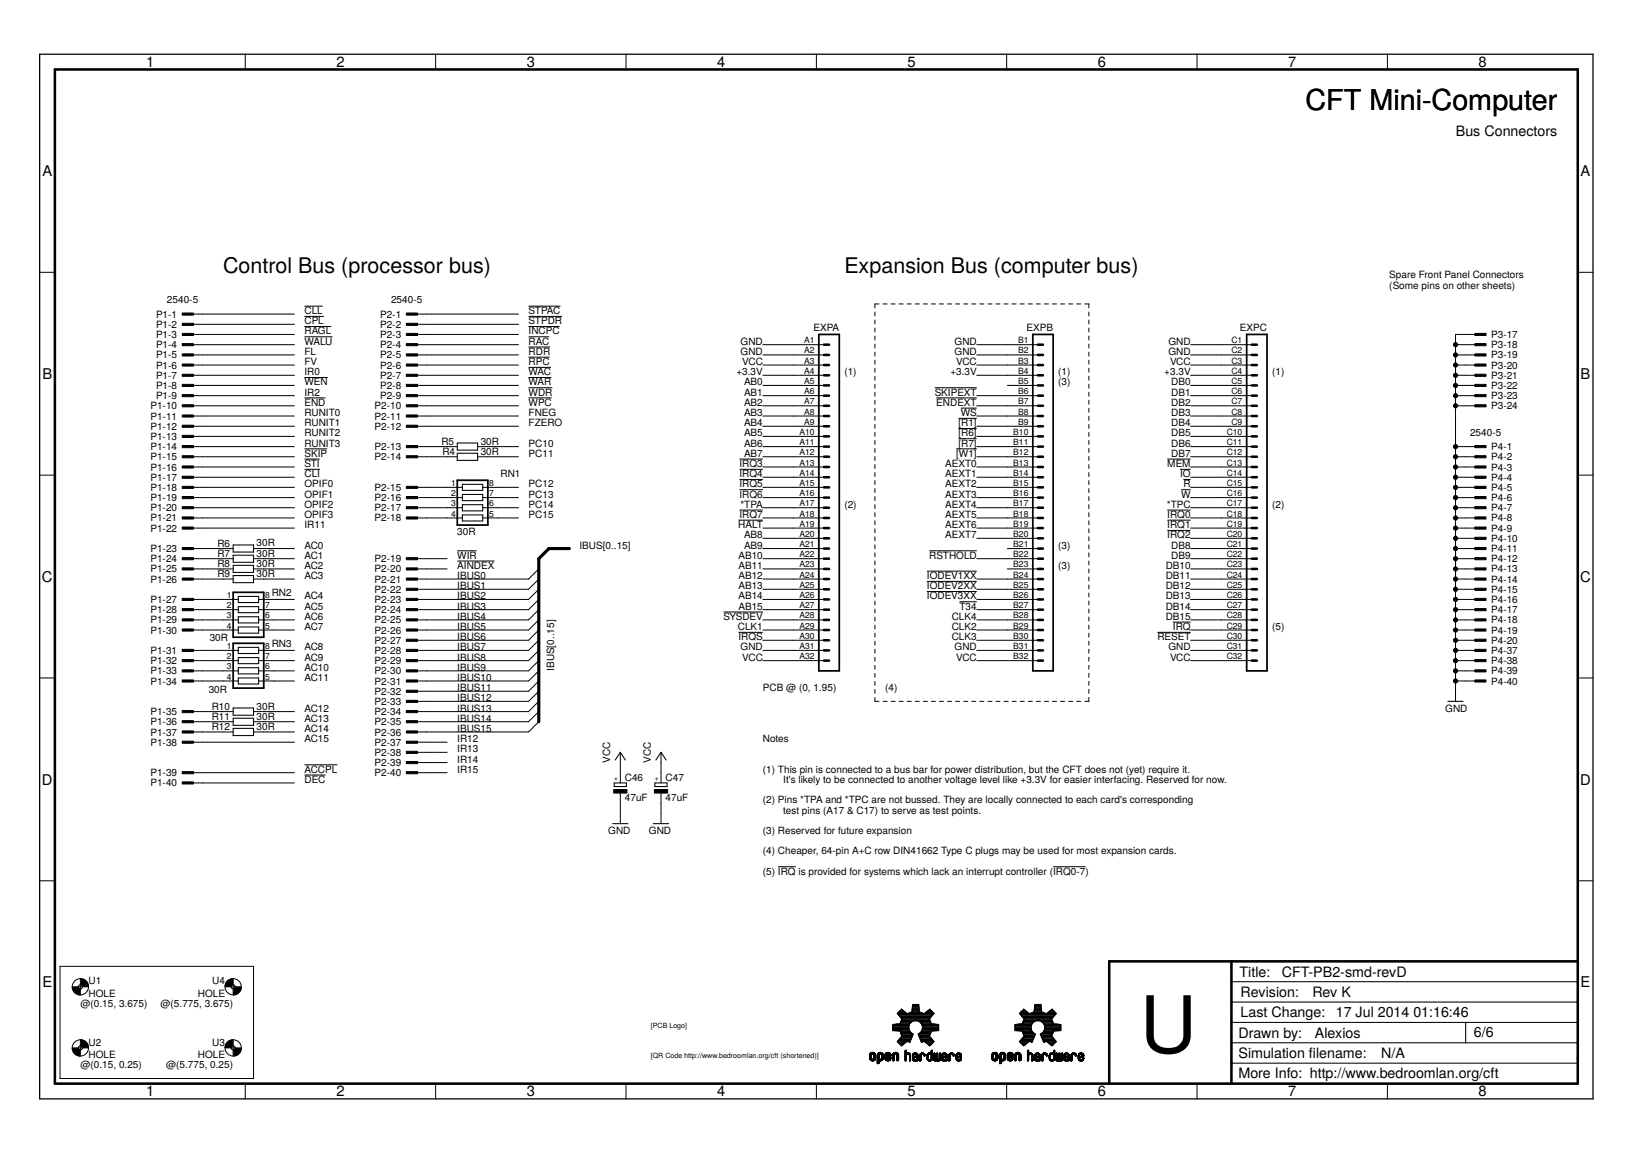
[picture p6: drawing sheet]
<svg xmlns="http://www.w3.org/2000/svg" width="297mm" height="210mm" viewBox="0 0 297 210" stroke-linecap="round" stroke-linejoin="round" font-family="sans-serif">
<defs><g id="words">
<text font-size="14.4" x="207.4" y="191.5">U</text>
<text font-size="5.2" x="237.6" y="20.1">CFT Mini-Computer</text>
<g font-size="3.9">
<text x="40.6" y="49.7">Control Bus (processor bus)</text>
<text x="153.7" y="49.7">Expansion Bus (computer bus)</text>
</g>
<g font-size="2.7">
<text x="26.6" y="12.2">1</text>
<text x="61.2" y="12.2">2</text>
<text x="95.9" y="12.2">3</text>
<text x="130.5" y="12.2">4</text>
<text x="165.2" y="12.2">5</text>
<text x="199.8" y="12.2">6</text>
<text x="234.5" y="12.2">7</text>
<text x="269.1" y="12.2">8</text>
<text x="7.7" y="32">A</text>
<text x="287.7" y="32">A</text>
<text x="7.7" y="68.9">B</text>
<text x="287.7" y="68.9">B</text>
<text x="7.6" y="105.8">C</text>
<text x="287.6" y="105.8">C</text>
<text x="7.6" y="142.7">D</text>
<text x="287.6" y="142.7">D</text>
<text x="7.7" y="179.6">E</text>
<text x="287.7" y="179.6">E</text>
<text x="26.6" y="199.4">1</text>
<text x="61.2" y="199.4">2</text>
<text x="95.9" y="199.4">3</text>
<text x="130.5" y="199.4">4</text>
<text x="165.2" y="199.4">5</text>
<text x="199.8" y="199.4">6</text>
<text x="234.5" y="199.4">7</text>
<text x="269.1" y="199.4">8</text>
</g>
<g font-size="2.6">
<text x="265" y="24.7">Bus Connectors</text>
<text x="225.6" y="177.6">Title:</text>
<text x="233.3" y="177.7">CFT-PB2-smd-revD</text>
<text x="225.8" y="181.3">Revision:</text>
<text x="225.8" y="185">Last Change:</text>
<text x="238.9" y="181.4">Rev K</text>
<text x="243.1" y="185">17 Jul 2014</text>
<text x="257.3" y="185">01:16:46</text>
<text x="225.4" y="188.8">Drawn by:</text>
<text x="239.3" y="188.8">Alexios</text>
<text x="268.3" y="188.7">6/6</text>
<text x="225.4" y="192.5">Simulation flename:</text>
<text x="225.4" y="196.2">More Info: http://www.bedroomlan.org/cft</text>
<text x="238.2" y="192.5">i</text>
<text x="251.4" y="192.5">N/A</text>
</g>
<g font-size="1.8">
<text x="252.9" y="50.6">Spare Front Panel Connectors</text>
<text x="252.9" y="52.5">(Some pins on other sheets)</text>
<text x="28.4" y="57.8">P1-1</text>
<text x="28.4" y="59.6">P1-2</text>
<text x="30.4" y="55.2">2540-5</text>
<text x="55.4" y="57.1">CLL</text>
<text x="55.4" y="59">CPL</text>
<text x="69.2" y="57.8">P2-1</text>
<text x="69.2" y="59.6">P2-2</text>
<text x="71.2" y="55.2">2540-5</text>
<text x="96.2" y="59">STPDR</text>
<text x="96.2" y="57.1">STPAC</text>
<text x="28.4" y="61.5">P1-3</text>
<text x="28.4" y="63.3">P1-4</text>
<text x="28.4" y="65.2">P1-5</text>
<text x="55.4" y="64.5">FL</text>
<text x="55.4" y="62.7">WALU</text>
<text x="55.4" y="60.8">RAGL</text>
<text x="69.2" y="61.5">P2-3</text>
<text x="69.2" y="63.3">P2-4</text>
<text x="69.2" y="65.2">P2-5</text>
<text x="96.2" y="60.8">INCPC</text>
<text x="96.2" y="64.5">RDR</text>
<text x="96.2" y="62.7">RAC</text>
<text x="134.8" y="64.5">GND</text>
<text x="134.8" y="62.7">GND</text>
<text x="148.1" y="60.3">EXPA</text>
<text x="173.7" y="64.5">GND</text>
<text x="173.7" y="62.7">GND</text>
<text x="186.9" y="60.3">EXPB</text>
<text x="212.7" y="64.5">GND</text>
<text x="212.7" y="62.7">GND</text>
<text x="225.7" y="60.3">EXPC</text>
<text x="271.4" y="61.5">P3-17</text>
<text x="271.4" y="63.3">P3-18</text>
<text x="271.4" y="65.2">P3-19</text>
<text x="28.4" y="67">P1-6</text>
<text x="28.4" y="68.9">P1-7</text>
<text x="28.4" y="70.8">P1-8</text>
<text x="55.4" y="66.4">FV</text>
<text x="55.4" y="68.3">IR0</text>
<text x="55.4" y="72">IR2</text>
<text x="55.4" y="70.1">WEN</text>
<text x="69.2" y="67">P2-6</text>
<text x="69.2" y="68.9">P2-7</text>
<text x="69.2" y="70.8">P2-8</text>
<text x="96.2" y="66.4">RPC</text>
<text x="96.2" y="70.1">WAR</text>
<text x="96.2" y="72">WDR</text>
<text x="96.2" y="68.3">WAC</text>
<text x="134" y="68.3">+3.3V</text>
<text x="135.1" y="66.4">VCC</text>
<text x="135.4" y="72">AB1</text>
<text x="135.4" y="70.1">AB0</text>
<text x="153.7" y="68.3">(1)</text>
<text x="170.1" y="72">SKIPEXT</text>
<text x="173" y="68.3">+3.3V</text>
<text x="174" y="66.4">VCC</text>
<text x="192.6" y="68.3">(1)</text>
<text x="192.6" y="70.1">(3)</text>
<text x="211.9" y="68.3">+3.3V</text>
<text x="213" y="66.4">VCC</text>
<text x="213.2" y="72">DB1</text>
<text x="213.2" y="70.1">DB0</text>
<text x="231.5" y="68.3">(1)</text>
<text x="271.4" y="67">P3-20</text>
<text x="271.4" y="68.9">P3-21</text>
<text x="271.4" y="70.8">P3-22</text>
<text x="27.4" y="74.5">P1-10</text>
<text x="27.4" y="76.3">P1-11</text>
<text x="28.4" y="72.6">P1-9</text>
<text x="55.4" y="75.7">RUNIT0</text>
<text x="55.4" y="77.5">RUNIT1</text>
<text x="55.4" y="73.8">END</text>
<text x="68.2" y="74.5">P2-10</text>
<text x="68.2" y="76.3">P2-11</text>
<text x="69.2" y="72.6">P2-9</text>
<text x="96.2" y="75.7">FNEG</text>
<text x="96.2" y="77.5">FZERO</text>
<text x="96.2" y="73.8">WPC</text>
<text x="135.4" y="77.5">AB4</text>
<text x="135.4" y="75.7">AB3</text>
<text x="135.4" y="73.8">AB2</text>
<text x="170.4" y="73.8">ENDEXT</text>
<text x="174.4" y="77.5">[R1]</text>
<text x="174.9" y="75.7">WS</text>
<text x="213.2" y="77.5">DB4</text>
<text x="213.2" y="75.7">DB3</text>
<text x="213.2" y="73.8">DB2</text>
<text x="271.4" y="72.6">P3-23</text>
<text x="271.4" y="74.5">P3-24</text>
<text x="27.4" y="78.2">P1-12</text>
<text x="27.4" y="80">P1-13</text>
<text x="27.4" y="81.9">P1-14</text>
<text x="27.4" y="83.7">P1-15</text>
<text x="55.4" y="79.4">RUNIT2</text>
<text x="55.4" y="81.2">RUNIT3</text>
<text x="55.4" y="83.1">SKIP</text>
<text x="68.2" y="78.2">P2-12</text>
<text x="68.2" y="81.9">P2-13</text>
<text x="68.2" y="83.7">P2-14</text>
<text x="80.3" y="80.9">R5</text>
<text x="80.5" y="82.7">R4</text>
<text x="87.5" y="82.7">30R</text>
<text x="87.5" y="80.9">30R</text>
<text x="96.2" y="81.2">PC10</text>
<text x="96.2" y="83.1">PC11</text>
<text x="135.4" y="83.1">AB7</text>
<text x="135.4" y="81.2">AB6</text>
<text x="135.4" y="79.4">AB5</text>
<text x="174" y="83.1">[W1]</text>
<text x="174.4" y="79.4">[R6]</text>
<text x="174.4" y="81.2">[R7]</text>
<text x="213.2" y="83.1">DB7</text>
<text x="213.2" y="81.2">DB6</text>
<text x="213.2" y="79.4">DB5</text>
<text x="267.6" y="79.3">2540-5</text>
<text x="271.4" y="81.9">P4-1</text>
<text x="271.4" y="83.7">P4-2</text>
<text x="27.4" y="85.6">P1-16</text>
<text x="27.4" y="87.4">P1-17</text>
<text x="27.4" y="89.3">P1-18</text>
<text x="55.4" y="88.6">OPIF0</text>
<text x="55.4" y="84.9">STI</text>
<text x="55.4" y="86.8">CLI</text>
<text x="68.2" y="89.3">P2-15</text>
<text x="91.1" y="86.8">RN1</text>
<text x="96.2" y="88.6">PC12</text>
<text x="134.6" y="84.9">IRQ3</text>
<text x="134.6" y="86.8">IRQ4</text>
<text x="134.6" y="88.6">IRQ5</text>
<text x="172" y="88.6">AEXT2</text>
<text x="172" y="86.8">AEXT1</text>
<text x="172" y="84.9">AEXT0</text>
<text x="212.5" y="84.9">MEM</text>
<text x="214.8" y="86.8">IO</text>
<text x="215.4" y="88.6">R</text>
<text x="271.4" y="85.6">P4-3</text>
<text x="271.4" y="87.4">P4-4</text>
<text x="271.4" y="89.3">P4-5</text>
<text x="27.4" y="91.1">P1-19</text>
<text x="27.4" y="93">P1-20</text>
<text x="27.4" y="94.9">P1-21</text>
<text x="55.4" y="90.5">OPIF1</text>
<text x="55.4" y="92.4">OPIF2</text>
<text x="55.4" y="94.2">OPIF3</text>
<text x="68.2" y="91.1">P2-16</text>
<text x="68.2" y="93">P2-17</text>
<text x="68.2" y="94.9">P2-18</text>
<text x="96.2" y="90.5">PC13</text>
<text x="96.2" y="92.4">PC14</text>
<text x="96.2" y="94.2">PC15</text>
<text x="134.6" y="94.2">IRQ7</text>
<text x="134.6" y="90.5">IRQ6</text>
<text x="134.8" y="92.4">*TPA</text>
<text x="153.7" y="92.4">(2)</text>
<text x="172" y="94.2">AEXT5</text>
<text x="172" y="92.4">AEXT4</text>
<text x="172" y="90.5">AEXT3</text>
<text x="212.4" y="92.4">*TPC</text>
<text x="212.5" y="94.2">IRQ0</text>
<text x="215" y="90.5">W</text>
<text x="231.5" y="92.4">(2)</text>
<text x="271.4" y="91.1">P4-6</text>
<text x="271.4" y="93">P4-7</text>
<text x="271.4" y="94.9">P4-8</text>
<text x="27.4" y="96.7">P1-22</text>
<text x="27.4" y="100.4">P1-23</text>
<text x="39.6" y="99.4">R6</text>
<text x="39.6" y="101.3">R7</text>
<text x="46.7" y="99.4">30R</text>
<text x="46.7" y="101.3">30R</text>
<text x="55.4" y="99.8">AC0</text>
<text x="55.4" y="101.6">AC1</text>
<text x="55.4" y="96.1">IR11</text>
<text x="83.2" y="97.4">30R</text>
<text x="83.2" y="101.6">WIR</text>
<text x="105.5" y="99.8">IBUS[0..15]</text>
<text x="134.4" y="96.1">HALT</text>
<text x="134.4" y="101.6">AB10</text>
<text x="135.4" y="99.8">AB9</text>
<text x="135.4" y="97.9">AB8</text>
<text x="169.1" y="101.6">RSTHOLD</text>
<text x="172" y="97.9">AEXT7</text>
<text x="172" y="96.1">AEXT6</text>
<text x="192.6" y="99.8">(3)</text>
<text x="212.5" y="97.9">IRQ2</text>
<text x="212.5" y="96.1">IRQ1</text>
<text x="213.2" y="101.6">DB9</text>
<text x="213.2" y="99.8">DB8</text>
<text x="271.4" y="96.7">P4-9</text>
<text x="271.4" y="98.6">P4-10</text>
<text x="271.4" y="100.4">P4-11</text>
<text x="27.4" y="102.3">P1-24</text>
<text x="27.4" y="104.1">P1-25</text>
<text x="27.4" y="106">P1-26</text>
<text x="39.6" y="103.1">R8</text>
<text x="39.6" y="105">R9</text>
<text x="46.7" y="103.1">30R</text>
<text x="46.7" y="105">30R</text>
<text x="55.4" y="103.5">AC2</text>
<text x="55.4" y="105.3">AC3</text>
<text x="68.2" y="102.3">P2-19</text>
<text x="68.2" y="104.1">P2-20</text>
<text x="68.2" y="106">P2-21</text>
<text x="68.2" y="107.8">P2-22</text>
<text x="83.2" y="105.3">IBUS0</text>
<text x="83.2" y="107.2">IBUS1</text>
<text x="83.2" y="103.5">AINDEX</text>
<text x="134.4" y="107.2">AB13</text>
<text x="134.4" y="105.3">AB12</text>
<text x="134.4" y="103.5">AB11</text>
<text x="168.7" y="107.2">IODEV2XX</text>
<text x="168.7" y="105.3">IODEV1XX</text>
<text x="192.6" y="103.5">(3)</text>
<text x="212.2" y="107.2">DB12</text>
<text x="212.2" y="105.3">DB11</text>
<text x="212.2" y="103.5">DB10</text>
<text x="271.4" y="102.3">P4-12</text>
<text x="271.4" y="104.1">P4-13</text>
<text x="271.4" y="106">P4-14</text>
<text x="271.4" y="107.8">P4-15</text>
<text x="27.4" y="109.7">P1-27</text>
<text x="27.4" y="111.5">P1-28</text>
<text x="27.4" y="113.4">P1-29</text>
<text x="49.5" y="108.5">RN2</text>
<text x="55.4" y="109">AC4</text>
<text x="55.4" y="110.9">AC5</text>
<text x="55.4" y="112.7">AC6</text>
<text x="68.2" y="109.7">P2-23</text>
<text x="68.2" y="111.5">P2-24</text>
<text x="68.2" y="113.4">P2-25</text>
<text x="83.2" y="109">IBUS2</text>
<text x="83.2" y="110.9">IBUS3</text>
<text x="83.2" y="112.7">IBUS4</text>
<text x="131.7" y="112.7">SYSDEV</text>
<text x="134.4" y="110.9">AB15</text>
<text x="134.4" y="109">AB14</text>
<text x="168.7" y="109">IODEV3XX</text>
<text x="173.2" y="112.7">CLK4</text>
<text x="174.6" y="110.9">T34</text>
<text x="212.2" y="112.7">DB15</text>
<text x="212.2" y="110.9">DB14</text>
<text x="212.2" y="109">DB13</text>
<text x="271.4" y="109.7">P4-16</text>
<text x="271.4" y="111.5">P4-17</text>
<text x="271.4" y="113.4">P4-18</text>
<text x="27.4" y="115.2">P1-30</text>
<text x="27.4" y="119">P1-31</text>
<text x="38.2" y="116.6">30R</text>
<text x="49.5" y="117.7">RN3</text>
<text x="55.4" y="114.6">AC7</text>
<text x="55.4" y="118.3">AC8</text>
<text x="68.2" y="115.2">P2-26</text>
<text x="68.2" y="117.1">P2-27</text>
<text x="68.2" y="119">P2-28</text>
<text x="83.2" y="114.6">IBUS5</text>
<text x="83.2" y="118.3">IBUS7</text>
<text x="83.2" y="116.5">IBUS6</text>
<text x="134.3" y="114.6">CLK1</text>
<text x="134.4" y="116.5">IRQS</text>
<text x="134.8" y="118.3">GND</text>
<text x="173.2" y="114.6">CLK2</text>
<text x="173.2" y="116.5">CLK3</text>
<text x="173.7" y="118.3">GND</text>
<text x="210.7" y="116.5">RESET</text>
<text x="212.7" y="118.3">GND</text>
<text x="213.5" y="114.6">IRQ</text>
<text x="231.5" y="114.6">(5)</text>
<text x="271.4" y="115.2">P4-19</text>
<text x="271.4" y="117.1">P4-20</text>
<text x="271.4" y="119">P4-37</text>
<text x="27.4" y="120.8">P1-32</text>
<text x="27.4" y="122.7">P1-33</text>
<text x="27.4" y="124.5">P1-34</text>
<text x="55.4" y="120.2">AC9</text>
<text x="55.4" y="122">AC10</text>
<text x="55.4" y="123.9">AC11</text>
<text x="68.2" y="120.8">P2-29</text>
<text x="68.2" y="122.7">P2-30</text>
<text x="68.2" y="124.5">P2-31</text>
<text x="83.2" y="120.2">IBUS8</text>
<text x="83.2" y="122">IBUS9</text>
<text x="83.2" y="123.9">IBUS10</text>
<text x="83.2" y="125.7">IBUS11</text>
<text x="100.8" y="122" transform="rotate(-90 100.8 122)">IBUS[0..15]</text>
<text x="135.1" y="120.2">VCC</text>
<text x="138.8" y="125.7">PCB @ (0, 1.95)</text>
<text x="161.1" y="125.7">(4)</text>
<text x="174" y="120.2">VCC</text>
<text x="213" y="120.2">VCC</text>
<text x="271.4" y="120.8">P4-38</text>
<text x="271.4" y="122.7">P4-39</text>
<text x="271.4" y="124.5">P4-40</text>
<text x="27.4" y="130.1">P1-35</text>
<text x="27.4" y="131.9">P1-36</text>
<text x="38" y="126.1">30R</text>
<text x="38.5" y="129.1">R10</text>
<text x="38.5" y="130.9">R11</text>
<text x="46.7" y="129.1">30R</text>
<text x="46.7" y="130.9">30R</text>
<text x="55.4" y="129.4">AC12</text>
<text x="55.4" y="131.3">AC13</text>
<text x="68.2" y="126.4">P2-32</text>
<text x="68.2" y="128.2">P2-33</text>
<text x="68.2" y="130.1">P2-34</text>
<text x="68.2" y="131.9">P2-35</text>
<text x="83.2" y="127.6">IBUS12</text>
<text x="83.2" y="129.4">IBUS13</text>
<text x="83.2" y="131.3">IBUS14</text>
<text x="263.1" y="129.4">GND</text>
<text x="27.4" y="133.8">P1-37</text>
<text x="27.4" y="135.6">P1-38</text>
<text x="38.5" y="132.8">R12</text>
<text x="46.7" y="132.8">30R</text>
<text x="55.4" y="133.1">AC14</text>
<text x="55.4" y="135">AC15</text>
<text x="68.2" y="133.8">P2-36</text>
<text x="68.2" y="135.6">P2-37</text>
<text x="68.2" y="137.5">P2-38</text>
<text x="83.2" y="133.1">IBUS15</text>
<text x="83.2" y="135">IR12</text>
<text x="83.2" y="136.8">IR13</text>
<text x="138.8" y="135">Notes</text>
<text x="27.4" y="141.2">P1-39</text>
<text x="27.4" y="143.1">P1-40</text>
<text x="55.4" y="140.6">ACCPL</text>
<text x="55.4" y="142.4">DEC</text>
<text x="68.2" y="139.3">P2-39</text>
<text x="68.2" y="141.2">P2-40</text>
<text x="83.2" y="138.7">IR14</text>
<text x="83.2" y="140.6">IR15</text>
<text x="111" y="138.7" transform="rotate(-90 111 138.7)">VCC</text>
<text x="113.7" y="142.1">C46</text>
<text x="118.5" y="138.7" transform="rotate(-90 118.5 138.7)">VCC</text>
<text x="121.1" y="142.1">C47</text>
<text x="138.8" y="140.6">(1) This pin is connected to a bus bar for power distribution, but the CFT does not (yet) require it.</text>
<text x="142.6" y="142.4">It's likely to be connected to another voltage level like +3.3V for easier interfacing. Reserved for now.</text>
<text x="113.7" y="145.8">47uF</text>
<text x="121.1" y="145.8">47uF</text>
<text x="138.8" y="146.1">(2) Pins *TPA and *TPC are not bussed. They are locally connected to each card's corresponding</text>
<text x="142.6" y="148">test pins (A17 &amp; C17) to serve as test points.</text>
<text x="110.7" y="151.7">GND</text>
<text x="118.1" y="151.7">GND</text>
<text x="138.8" y="151.7">(3) Reserved for future expansion</text>
<text x="138.8" y="155.4">(4) Cheaper, 64-pin A+C row DIN41662 Type C plugs may be used for most expansion cards.</text>
<text x="138.8" y="159.1">(5) IRQ is provided for systems which lack an interrupt controller (IRQ0-7)</text>
<text x="16.1" y="179.1">U1</text>
<text x="38.6" y="179.1">U4</text>
<text x="14.6" y="183.2">@(0.15, 3.675)</text>
<text x="16.1" y="181.3">HOLE</text>
<text x="29.2" y="183.2">@(5.775, 3.675)</text>
<text x="36" y="181.3">HOLE</text>
<text x="16.1" y="190.2">U2</text>
<text x="38.6" y="190.2">U3</text>
<text x="14.6" y="194.3">@(0.15, 0.25)</text>
<text x="16.1" y="192.4">HOLE</text>
<text x="30.2" y="194.3">@(5.775, 0.25)</text>
<text x="36" y="192.4">HOLE</text>
</g>
<g font-size="1.6">
<text x="146.4" y="62.4">A1</text>
<text x="146.4" y="64.3">A2</text>
<text x="185.3" y="62.4">B1</text>
<text x="185.3" y="64.3">B2</text>
<text x="224.1" y="62.4">C1</text>
<text x="224.1" y="64.3">C2</text>
<text x="146.4" y="66.1">A3</text>
<text x="146.4" y="68">A4</text>
<text x="146.4" y="69.9">A5</text>
<text x="146.4" y="71.7">A6</text>
<text x="185.3" y="66.1">B3</text>
<text x="185.3" y="68">B4</text>
<text x="185.3" y="69.9">B5</text>
<text x="185.3" y="71.7">B6</text>
<text x="224.1" y="66.1">C3</text>
<text x="224.1" y="68">C4</text>
<text x="224.1" y="69.9">C5</text>
<text x="224.1" y="71.7">C6</text>
<text x="146.4" y="73.6">A7</text>
<text x="146.4" y="75.4">A8</text>
<text x="146.4" y="77.3">A9</text>
<text x="185.3" y="73.6">B7</text>
<text x="185.3" y="75.4">B8</text>
<text x="185.3" y="77.3">B9</text>
<text x="224.1" y="73.6">C7</text>
<text x="224.1" y="75.4">C8</text>
<text x="224.1" y="77.3">C9</text>
<text x="145.5" y="79.1">A10</text>
<text x="145.5" y="81">A11</text>
<text x="145.5" y="82.8">A12</text>
<text x="184.4" y="79.1">B10</text>
<text x="184.4" y="81">B11</text>
<text x="184.4" y="82.8">B12</text>
<text x="223.3" y="79.1">C10</text>
<text x="223.3" y="81">C11</text>
<text x="223.3" y="82.8">C12</text>
<text x="82.1" y="88.4">1</text>
<text x="89.1" y="88.4">8</text>
<text x="145.5" y="84.7">A13</text>
<text x="145.5" y="86.5">A14</text>
<text x="145.5" y="88.4">A15</text>
<text x="184.4" y="84.7">B13</text>
<text x="184.4" y="86.5">B14</text>
<text x="184.4" y="88.4">B15</text>
<text x="223.3" y="84.7">C13</text>
<text x="223.3" y="86.5">C14</text>
<text x="223.3" y="88.4">C15</text>
<text x="82.1" y="90.2">2</text>
<text x="82.1" y="92.1">3</text>
<text x="82.1" y="93.9">4</text>
<text x="89.1" y="93.9">5</text>
<text x="89.1" y="92.1">6</text>
<text x="89.1" y="90.2">7</text>
<text x="145.5" y="90.2">A16</text>
<text x="145.5" y="92.1">A17</text>
<text x="145.5" y="93.9">A18</text>
<text x="145.5" y="95.8">A19</text>
<text x="184.4" y="90.2">B16</text>
<text x="184.4" y="92.1">B17</text>
<text x="184.4" y="93.9">B18</text>
<text x="184.4" y="95.8">B19</text>
<text x="223.3" y="90.2">C16</text>
<text x="223.3" y="92.1">C17</text>
<text x="223.3" y="93.9">C18</text>
<text x="223.3" y="95.8">C19</text>
<text x="145.5" y="97.7">A20</text>
<text x="145.5" y="99.5">A21</text>
<text x="145.5" y="101.4">A22</text>
<text x="184.4" y="97.7">B20</text>
<text x="184.4" y="99.5">B21</text>
<text x="184.4" y="101.4">B22</text>
<text x="223.3" y="97.7">C20</text>
<text x="223.3" y="99.5">C21</text>
<text x="223.3" y="101.4">C22</text>
<text x="145.5" y="103.2">A23</text>
<text x="145.5" y="105.1">A24</text>
<text x="145.5" y="106.9">A25</text>
<text x="184.4" y="103.2">B23</text>
<text x="184.4" y="105.1">B24</text>
<text x="184.4" y="106.9">B25</text>
<text x="223.3" y="103.2">C23</text>
<text x="223.3" y="105.1">C24</text>
<text x="223.3" y="106.9">C25</text>
<text x="41.3" y="110.6">2</text>
<text x="41.3" y="112.5">3</text>
<text x="41.3" y="108.8">1</text>
<text x="48.3" y="112.5">6</text>
<text x="48.3" y="110.6">7</text>
<text x="48.3" y="108.8">8</text>
<text x="145.5" y="108.8">A26</text>
<text x="145.5" y="110.6">A27</text>
<text x="145.5" y="112.5">A28</text>
<text x="184.4" y="108.8">B26</text>
<text x="184.4" y="110.6">B27</text>
<text x="184.4" y="112.5">B28</text>
<text x="223.3" y="108.8">C26</text>
<text x="223.3" y="110.6">C27</text>
<text x="223.3" y="112.5">C28</text>
<text x="41.3" y="114.3">4</text>
<text x="41.3" y="119.9">2</text>
<text x="41.3" y="118">1</text>
<text x="48.3" y="114.3">5</text>
<text x="48.3" y="119.9">7</text>
<text x="48.3" y="118">8</text>
<text x="145.5" y="114.3">A29</text>
<text x="145.5" y="116.2">A30</text>
<text x="145.5" y="118">A31</text>
<text x="145.5" y="119.9">A32</text>
<text x="184.4" y="114.3">B29</text>
<text x="184.4" y="116.2">B30</text>
<text x="184.4" y="118">B31</text>
<text x="184.4" y="119.9">B32</text>
<text x="223.3" y="114.3">C29</text>
<text x="223.3" y="116.2">C30</text>
<text x="223.3" y="118">C31</text>
<text x="223.3" y="119.9">C32</text>
<text x="41.3" y="121.8">3</text>
<text x="41.3" y="123.6">4</text>
<text x="48.3" y="123.6">5</text>
<text x="48.3" y="121.8">6</text>
</g>
<g font-size="1.3">
<text x="112.5" y="142.1" transform="rotate(-90 112.5 142.1)">+</text>
<text x="119.9" y="142.1" transform="rotate(-90 119.9 142.1)">+</text>
<text x="118.5" y="186.9">[PCB Logo]</text>
<text x="118.5" y="192.5">[QR Code http://www.bedroomlan.org/cft (shortened)]</text>
</g>
</g></defs>
<g fill="none" stroke="#000" stroke-width=".18">
<path d="M10 12.6h277.2v184.5h-277.2zM44.6 9.9v2.7M79.3 9.9v2.7M113.9 9.9v2.7M148.6 9.9v2.7M183.2 9.9v2.7M217.9 9.9v2.7M252.5 9.9v2.7M7.2 49.5h2.8M35 57.1h18.6M35 59h18.6M55.4 57.6h3.5"/>
<path d="M55.4 59.4h4.9M55.4 55.7h3.4M75.8 57.1h18.6M75.8 59h18.6M96.2 57.6h6.1M96.2 59.4h5.7M96.2 55.7h5.8M159.2 56.7v.8M159.2 58.2v.7M159.2 59.7v.7M160 55.3h-.8v.7M160.7 55.3h.8"/>
<path d="M162.2 55.3h.7M163.6 55.3h.8M165.1 55.3h.8M166.6 55.3h.7M168.1 55.3h.7M169.5 55.3h.8M171 55.3h.7M172.5 55.3h.7M173.9 55.3h.8M175.4 55.3h.7M176.9 55.3h.7M178.3 55.3h.8"/>
<path d="M179.8 55.3h.8M181.3 55.3h.7M182.8 55.3h.7M184.2 55.3h.8M185.7 55.3h.7M187.2 55.3h.7M188.6 55.3h.8M190.1 55.3h.7M191.6 55.3h.7M193 55.3h.8M194.5 55.3h.7M196 55.3h.7"/>
<path d="M197.4 55.3h.8v.7M198.2 56.7v.8M198.2 58.2v.7M198.2 59.7v.7M287.2 49.5h2.7M35 62.7h18.6M35 64.6h18.6M35 66.4h18.6M35 68.3h18.6M35 70.1h18.6M35 72h18.6M35 73.8h18.6"/>
<path d="M35 75.7h18.6M35 77.5h18.6M35 79.4h18.6M35 60.8h18.6M55.4 72.4h3.8M55.4 61.3h5.1M55.4 68.7h4.2M75.8 62.7h18.6M75.8 64.6h18.6M75.8 66.4h18.6M75.8 68.3h18.6M75.8 70.1h18.6"/>
<path d="M75.8 72h18.6M75.8 73.8h18.6M75.8 75.7h18.6M75.8 77.5h18.6M75.8 60.8h18.6M96.2 70.5h4.3M96.2 72.4h4.2M96.2 65h3.8M96.2 63.1h3.9M96.2 61.3h3.8M96.2 68.7h4.2M96.2 66.8h4.1"/>
<path d="M138.9 62.7h11.1M138.9 64.6h11.1M138.9 66.4h11.1M138.9 68.3h11.1M138.9 70.1h11.1M138.9 72h11.1M138.9 73.8h11.1M138.9 75.7h11.1M138.9 77.5h11.1M138.9 79.4h11.1M159.2 61.1v.7M159.2 62.6v.7"/>
<path d="M159.2 64.1v.7M159.2 65.5v.7M159.2 67v.7M159.2 68.4v.8M159.2 69.9v.7M159.2 71.4v.7M159.2 72.8v.7M159.2 74.3v.7M159.2 75.7v.8M159.2 77.2v.7M159.2 78.7v.7M170.1 70.5h7.7"/>
<path d="M170.4 72.4h7.4M174.4 76.1h3.4M174.4 77.9h3.4M174.4 79.8h3.4M174.9 74.2h2.9M177.8 62.7h11.1M177.8 64.6h11.1M177.8 66.4h11.1M177.8 68.3h11.1M177.8 72h11.1M177.8 73.8h11.1M177.8 75.7h11.1"/>
<path d="M177.8 77.5h11.1M177.8 79.4h11.1M183.3 70.1h5.6M198.2 61.1v.7M198.2 62.6v.7M198.2 64.1v.7M198.2 65.5v.7M198.2 67v.7M198.2 68.4v.8M198.2 69.9v.7M198.2 71.4v.7M198.2 72.8v.7"/>
<path d="M198.2 74.3v.7M198.2 75.7v.8M198.2 77.2v.7M198.2 78.7v.7M216.7 62.7h11.1M216.7 64.6h11.1M216.7 66.4h11.1M216.7 68.3h11.1M216.7 70.1h11.1M216.7 72h11.1M216.7 73.8h11.1M216.7 75.7h11.1"/>
<path d="M216.7 77.5h11.1M216.7 79.4h11.1M264.9 62.7h3.7M264.9 64.6h3.7M264.9 66.4h3.7M264.9 68.3h3.7M264.9 70.1h3.7M264.9 72h3.7M264.9 73.8h3.7M268.6 60.8h-3.7v66.8M7.2 86.4h2.8M35 81.2h18.6"/>
<path d="M35 83.1h18.6M35 84.9h18.6M35 86.8h18.6M35 88.6h18.6M35 90.5h18.6M35 92.4h18.6M35 94.2h18.6M35 96.1h18.6M35 99.8h7.4M46.1 99.8h7.5M55.4 83.5h2.8M55.4 85.4h2.9"/>
<path d="M55.4 81.6h4.1M75.8 81.2h7.4M75.8 83.1h7.4M75.8 88.6h8.4M75.8 90.5h8.4M75.8 92.4h8.4M75.8 94.2h8.4M86.9 81.2h7.5M86.9 83.1h7.5M87.9 88.6h6.5M87.9 90.5h6.5M87.9 92.4h6.5"/>
<path d="M87.9 94.2h6.5M134.4 94.6h4.5M134.6 83.5h4.3M134.6 85.4h4.3M134.6 87.2h4.3M134.6 89.1h4.3M134.6 92.8h4.3M138.9 81.2h11.1M138.9 83.1h11.1M138.9 84.9h11.1M138.9 86.8h11.1M138.9 88.6h11.1"/>
<path d="M138.9 90.5h11.1M138.9 92.4h11.1M138.9 94.2h11.1M138.9 96.1h11.1M138.9 97.9h11.1M138.9 99.8h11.1M159.2 80.1v.7M159.2 81.6v.7M159.2 83v.8M159.2 84.5v.7M159.2 86v.7M159.2 87.4v.7"/>
<path d="M159.2 88.9v.7M159.2 90.3v.8M159.2 91.8v.7M159.2 93.3v.7M159.2 94.7v.7M159.2 96.2v.7M159.2 97.6v.8M159.2 99.1v.7M174 81.6h3.8M177.8 81.2h11.1M177.8 83.1h11.1M177.8 84.9h11.1"/>
<path d="M177.8 86.8h11.1M177.8 88.6h11.1M177.8 90.5h11.1M177.8 92.4h11.1M177.8 94.2h11.1M177.8 96.1h11.1M177.8 97.9h11.1M183.3 99.8h5.6M198.2 80.1v.7M198.2 81.6v.7M198.2 83v.8M198.2 84.5v.7"/>
<path d="M198.2 86v.7M198.2 87.4v.7M198.2 88.9v.7M198.2 90.3v.8M198.2 91.8v.7M198.2 93.3v.7M198.2 94.7v.7M198.2 96.2v.7M198.2 97.6v.8M198.2 99.1v.7M212.4 83.5h4.3M212.4 94.6h4.3"/>
<path d="M212.4 92.8h4.3M212.4 96.5h4.3M214.8 85.4h1.9M215 89.1h1.7M215.4 87.2h1.3M216.7 81.2h11.1M216.7 83.1h11.1M216.7 84.9h11.1M216.7 86.8h11.1M216.7 88.6h11.1M216.7 90.5h11.1M216.7 92.4h11.1"/>
<path d="M216.7 94.2h11.1M216.7 96.1h11.1M216.7 97.9h11.1M216.7 99.8h11.1M264.9 81.2h3.7M264.9 83.1h3.7M264.9 84.9h3.7M264.9 86.8h3.7M264.9 88.6h3.7M264.9 90.5h3.7M264.9 92.4h3.7M264.9 94.2h3.7"/>
<path d="M264.9 96.1h3.7M264.9 97.9h3.7M264.9 99.8h3.7M287.2 86.4h2.7M35 101.6h7.4M35 103.5h7.4M35 105.3h7.4M35 109h8.4M35 110.9h8.4M35 112.8h8.4M35 114.6h8.4M35 118.3h8.4"/>
<path d="M46.1 101.6h7.5M46.1 103.5h7.5M46.1 105.3h7.5M47.1 109h6.5M47.1 110.9h6.5M47.1 112.8h6.5M47.1 114.6h6.5M47.1 118.3h6.5M75.8 101.6h5.6M75.8 103.5h5.6M83.2 100.2h3.6M83.2 102h6.8"/>
<path d="M98.1 103.5l-1.9 1.8h-20.4M98.1 105.3l-1.9 1.9h-20.4M98.1 107.2l-1.9 1.8h-20.4M98.1 109l-1.9 1.9h-20.4M98.1 110.9l-1.9 1.9h-20.4M98.1 112.8l-1.9 1.8h-20.4M98.1 114.6l-1.9 1.9h-20.4M98.1 116.5l-1.9 1.8h-20.4M98.1 118.3l-1.9 1.9h-20.4M131.7 111.3h7.2M134.4 115h4.5M138.9 101.6h11.1"/>
<path d="M138.9 103.5h11.1M138.9 105.3h11.1M138.9 107.2h11.1M138.9 109h11.1M138.9 110.9h11.1M138.9 112.8h11.1M138.9 114.6h11.1M138.9 116.5h11.1M138.9 118.3h11.1M159.2 100.6v.7M159.2 102v.7M159.2 103.5v.7"/>
<path d="M159.2 104.9v.8M159.2 106.4v.7M159.2 107.9v.7M159.2 109.3v.7M159.2 110.8v.7M159.2 112.2v.8M159.2 113.7v.7M159.2 115.2v.7M159.2 116.6v.7M159.2 118.1v.7M159.2 119.5v.8M168.7 107.6h9.1"/>
<path d="M168.7 105.7h9.1M168.7 103.9h9.1M169.1 100.2h8.7M174.6 109.5h3.2M177.8 101.6h11.1M177.8 105.3h11.1M177.8 107.2h11.1M177.8 109h11.1M177.8 110.9h11.1M177.8 112.8h11.1M177.8 114.6h11.1M177.8 116.5h11.1"/>
<path d="M177.8 118.3h11.1M183.3 103.5h5.6M198.2 100.6v.7M198.2 102v.7M198.2 103.5v.7M198.2 104.9v.8M198.2 106.4v.7M198.2 107.9v.7M198.2 109.3v.7M198.2 110.8v.7M198.2 112.2v.8M198.2 113.7v.7"/>
<path d="M198.2 115.2v.7M198.2 116.6v.7M198.2 118.1v.7M198.2 119.5v.8M210.7 115h6M213.5 113.2h3.2M216.7 101.6h11.1M216.7 103.5h11.1M216.7 105.3h11.1M216.7 107.2h11.1M216.7 109h11.1M216.7 110.9h11.1"/>
<path d="M216.7 112.8h11.1M216.7 114.6h11.1M216.7 116.5h11.1M216.7 118.3h11.1M264.9 101.6h3.7M264.9 103.5h3.7M264.9 105.3h3.7M264.9 107.2h3.7M264.9 109h3.7M264.9 110.9h3.7M264.9 112.8h3.7M264.9 114.6h3.7"/>
<path d="M264.9 116.5h3.7M264.9 118.3h3.7M7.2 123.3h2.8M35 120.2h8.4M35 122h8.4M35 123.9h8.4M35 129.4h7.4M35 131.3h7.4M35 133.1h7.4M35 135h18.6M46.1 129.4h7.5M46.1 131.3h7.5"/>
<path d="M46.1 133.1h7.5M47.1 120.2h6.5M47.1 122h6.5M47.1 123.9h6.5M55.4 139.1h6M75.8 135h5.6M75.8 136.8h5.6M75.8 138.7h5.6M98.1 120.2l-1.9 1.8h-20.4M98.1 122l-1.9 1.9h-20.4M98.1 127.6l-1.9 1.8h-20.4M98.1 129.4l-1.9 1.9h-20.4"/>
<path d="M98.1 131.3l-1.9 1.8h-20.4M98.1 123.9l-1.9 1.8h-20.4M98.1 125.7l-1.9 1.9h-20.4M112.9 136.8v5.6M120.3 136.8v5.6M138.9 120.2h11.1M159.2 126.9v.7h.8M159.2 121v.7M159.2 122.5v.7M159.2 123.9v.8M159.2 125.4v.7M160.7 127.6h.8"/>
<path d="M162.2 127.6h.7M163.6 127.6h.8M165.1 127.6h.8M166.6 127.6h.7M168.1 127.6h.7M169.5 127.6h.8M171 127.6h.7M172.5 127.6h.7M173.9 127.6h.8M175.4 127.6h.7M176.9 127.6h.7M177.8 120.2h11.1"/>
<path d="M178.3 127.6h.8M179.8 127.6h.8M181.3 127.6h.7M182.8 127.6h.7M184.2 127.6h.8M185.7 127.6h.7M187.2 127.6h.7M188.6 127.6h.8M190.1 127.6h.7M191.6 127.6h.7M193 127.6h.8M194.5 127.6h.7"/>
<path d="M196 127.6h.7M198.2 126.9v.7h-.8M198.2 121v.7M198.2 122.5v.7M198.2 123.9v.8M198.2 125.4v.7M216.7 120.2h11.1M264.9 120.2h3.7M264.9 122h3.7M264.9 123.9h3.7M287.2 123.3h2.7M35 140.5h18.6"/>
<path d="M35 142.4h18.6M55.4 141h3.8M75.8 140.5h5.6M112.9 144.3v5.5M120.3 144.3v5.5M141.6 157.6h3.2M191.7 157.6h5.9M7.2 160.2h2.8M10.9 175.8h35.2v20.4h-35.2zM14.3 179.5h.7M14.6 179.1v.8M42.1 179.5h.7"/>
<path d="M42.4 179.1v.8M287.2 160.2h2.7M14.3 190.6h.7M14.6 190.2v.8M42.1 190.6h.7M42.4 190.2v.8M44.6 197.1v2.8M79.3 197.1v2.8M113.9 197.1v2.8M148.6 197.1v2.8M158.3 192.5h.3M158.3 192.4h.3"/>
<path d="M158.3 192.3h.3M158.3 192.2h.3M158.3 192.1h.3M158.3 192h.3M158.3 191.9h.3M158.3 192.6h.4M158.3 192.6h.3M158.3 191.8h.3M158.3 192.6l.4 .1M158.3 192.7h1M158.3 191.7h1M158.4 192.7h.9"/>
<path d="M158.4 191.7h.9M158.4 191.6h.9M158.4 192.8h.8M158.4 191.6h.8M158.5 192.9h.7M158.5 191.5h.7M158.5 191.5h.6M158.6 192.9h.5M158.7 193h.3M158.7 191.8h-.4M158.7 191.4h.3M158.7 191.7h-.4"/>
<path d="M158.9 191.7h.4M158.9 192.7h.4M159 192.6h.3M159 191.8h.3M159 191.8l.4 .1M159.1 192.5h.3M159.1 192.4h.3M159.1 192.3h.3M159.1 192.2h.3M159.1 192.1h.3M159.1 192h.3M159.1 191.9h.3"/>
<path d="M159.4 192.5h-.4M159.7 193.3h.3M159.7 193.2h.3M159.7 193.1h.3M159.7 193h.3M159.7 192.7h1M159.7 192.6l.4 .1M159.7 192.6h.4M159.7 192.6h.3M159.7 192.5h.3M159.7 192.4h.3M159.7 192.3h.3"/>
<path d="M159.7 192.2h.3M159.7 192.1h.3M159.7 192h.3M159.7 191.9h.3M159.7 193.5h.1M159.7 191.7h1M159.8 191.7h.9M159.8 191.6h.9M159.8 191.6h.8M159.9 191.5h.7M159.9 193.4h-.2M159.9 191.5h.6"/>
<path d="M160 193.4h-.3M160 191.8l-.3 .1M160.1 193h.3M160.1 191.8h-.4M160.1 191.4h.3M160.1 191.7h-.4M160.3 191.7h.4M160.3 192.7h.4M160.4 191.8h.3M160.4 192.6h.3M160.4 191.8l.4 .1M160.4 192.5h.4"/>
<path d="M160.5 192.5h.3M160.5 191.9h.3M160.5 192.9h-.8M160.5 192.4h.3M160.5 192.3h.3M160.5 192.2h.3M160.5 192.1h.3M160.5 192h.3M160.6 192.9h-.9M160.6 192.8h-.9M160.7 192.8h-1M160.7 192.6h-.3"/>
<path d="M161.1 192.6l.4 .1M161.1 192.6h.4M161.1 192.6h.3M161.1 192.5h.3M161.1 192.1h1M161.1 192l.3 .1M161.1 192h.3M161.1 191.8h.3M161.1 192.7h1M161.1 191.7h1M161.2 192.7h.9M161.2 191.7h.9"/>
<path d="M161.2 191.6h.9M161.2 192.8h.8M161.2 191.6h.8M161.3 191.5h.7M161.3 192.9h.6M161.3 191.5h.6M161.4 192.9h.5M161.4 191.9h-.3M161.5 192.4h-.4M161.5 192.1h.6M161.5 191.8h-.4M161.5 193h.3"/>
<path d="M161.5 191.4h.2M161.5 191.7h-.4M161.6 192.4h-.5M161.6 192h.5M161.6 192.3h-.5M161.7 192h.4M161.7 191.7h.4M161.8 192.3h-.7M161.8 191.8h.3M161.8 192.6h.3M161.8 191.9h.3M161.8 192.5h.3"/>
<path d="M161.9 192.5h.2M161.9 192.4h.2M161.9 192.2l-.8 .1M162 192.3h.1M162 192.2h-.9M162.1 192.2h-1M162.1 192.3h.1M162.1 192.6l-.4 .1M162.1 192.6h-.3M162.5 192.9h.2M162.5 192.8h.3M162.5 192.7h.3"/>
<path d="M162.5 192.6h.3M162.5 192.5h.3M162.5 192.4h.3M162.5 192.3h.3M162.5 192.2h.3M162.5 192.1h.3M162.5 192h.3M162.5 191.9h.3M162.5 193h.1M162.6 191.7h.9M162.6 191.6h.8M162.7 191.5h.7"/>
<path d="M162.7 191.5h.6M162.8 192.9h-.3M162.8 191.9h-.3M162.8 191.8l-.3 .1M162.9 191.8h-.4M162.9 191.4h.3M162.9 191.7h-.4M163.1 191.7h.4M163.2 191.8h.3M163.2 191.8l.4 .1M163.3 192.8h.3M163.3 192.7h.3"/>
<path d="M163.3 192.6h.3M163.3 192.5h.3M163.3 192.4h.3M163.3 192.3h.3M163.3 192.2h.3M163.3 192.1h.3M163.3 192h.3M163.3 191.9h.3M163.3 193h.1M163.5 192.9h-.2M163.5 191.7h-1M163.6 192.9h-.3"/>
<path d="M164.8 192.9h.2M164.8 192.8h.2M164.8 192.7h.2M164.8 192.6h.2M164.8 192.5h.2M164.8 192.4h.2M164.8 192.3h.2M164.8 192.2h.2M164.8 192.1h.2M164.8 192h.2M164.8 191.9h.2M164.8 191.7h.9"/>
<path d="M164.8 191.6l.8 .1M164.8 191.6h.8M164.8 191.6h.7M164.8 191.5h.2M164.8 191.4h.2M164.8 191.3h.2M164.8 191.2h.2M164.8 191.1h.2M164.8 191h.2M164.9 193h-.1M165 192.9h-.2M165 191.8l-.2 .1"/>
<path d="M165.1 191.5h.3M165.1 191.8h-.3M165.2 191.7h-.4M165.3 191.7h.4M165.4 191.8h.3M165.5 191.8l.2 .1M165.5 191.9h.2M165.5 193h.2M165.5 192.9h.2M165.5 192.8h.2M165.5 192.7h.2M165.5 192.6h.2"/>
<path d="M165.5 192.5h.2M165.5 192.4h.2M165.5 192.3h.2M165.5 192.2h.2M165.5 192.1h.2M165.5 192h.2M165.7 192.9h-.2M166.1 192.6h.2M166.1 192h.2M166.1 192.7l.3 .1M166.1 192.7h.2M166.1 192.5h.3"/>
<path d="M166.1 192.1h.1M166.1 191.9h.2M166.1 192.8h.6M166.2 192.9h.5M166.2 191.7h.8M166.2 191.7h.7M166.3 192l-.2 .1M166.3 191.6h.6M166.3 192h-.2M166.3 192.6h-.2M166.3 192.3h.8M166.3 191.9h-.2"/>
<path d="M166.3 193h.4M166.3 192.5h-.2M166.3 191.6h.5M166.4 191.8l-.3 .1M166.4 192.2h.7M166.4 191.5h.4M166.4 191.8h-.3M166.5 192.4h-.4M166.5 193h.1M166.5 192.2h.6M166.6 192.8h.1M166.6 192.4h-.5"/>
<path d="M166.6 192.1h.5M166.7 192.1h.4M166.7 192.3h-.5M166.7 191.8h.3M166.8 191.8h.2M166.8 192h.3M166.8 191.9h.3M166.9 192.9h.2M166.9 192.8h.2M166.9 192.7h.2M166.9 192.6h.2M166.9 192.5h.2"/>
<path d="M166.9 192.4h.2M166.9 192.3h.2M166.9 192h.2M167 193h-.1M167 191.7h-.8M167.1 192.9h-.2M167.1 192.3h-.9M167.4 192.9h.2M167.4 192.8h.2M167.4 192.7h.2M167.4 192.6h.2M167.4 192.5h.2"/>
<path d="M167.4 192.4h.2M167.4 192.3h.2M167.4 192.2h.2M167.4 192.1h.2M167.4 192h.2M167.4 191.9h.2M167.5 191.7h.8M167.5 193h-.1M167.6 191.6h.6M167.6 192.9h-.2M167.6 191.6h.5M167.7 191.8l-.3 .1"/>
<path d="M167.7 191.5h.4M167.8 191.8h-.4M168 191.8h.4M168.1 191.8l.3 .1M168.1 191.9h.3M168.2 191.9h.2M168.2 192h.2M168.3 191.7h-.8M168.3 192l-.1 .1M168.4 192h-.2M168.7 192.6h.3M168.7 192.5h.2"/>
<path d="M168.7 192.4h.2M168.7 192.3h.2M168.7 192.2h.2M168.7 192.1h.2M168.7 192h.2M168.7 191.9h.3M168.7 192.6l.3 .1M168.8 192.7h.3M168.8 192.7l.4 .1M168.8 192.8h.8M168.8 191.7h.9M168.9 192.9h.7"/>
<path d="M168.9 191.6h.8M168.9 192.9h.6M169 191.9h-.3M169 191.6h.7M169 193h.4M169 191.8l-.3 .1M169.1 191.5h.3M169.1 191.8h-.3M169.2 193h.1M169.2 191.7h-.4M169.2 191.7h.5M169.4 191.8h.3"/>
<path d="M169.5 192.6h.2M169.5 191.9h.2M169.5 192.5h.2M169.5 192.4h.2M169.5 192.3h.2M169.5 192.2h.2M169.5 192.1h.2M169.5 192h.2M169.5 191.5h.2M169.5 191.4h.2M169.5 191.3h.2M169.5 191.2h.2"/>
<path d="M169.5 191.1h.2M169.6 191h.1M169.7 192.7l-.4 .1M169.7 192.7h-.3M169.7 192.6h-.2M169.9 192.7l.3 .1M169.9 192.7h.3M169.9 192.6l.3 .1M169.9 192.6h.2M169.9 192.5h.2M169.9 192.4h.2M169.9 192.3h.2"/>
<path d="M169.9 192.2h.2M169.9 192.1h.2M169.9 192h.2M169.9 191.9h.2M169.9 191.8h.2M169.9 191.7h.2M169.9 191.6h.2M169.9 192.8h1.2M170 192.9h1.1M170 191.6h.1M170.1 191.5h.1M170.1 193h.4"/>
<path d="M170.3 193h.1M170.3 192.8h.5M170.4 192.7h.3M170.4 192.6h.3M170.4 192.6h.2M170.4 192.5h.2M170.4 192.4h.2M170.4 192.3h.2M170.4 192.2h.2M170.4 192.1h.2M170.4 192h.2M170.4 191.9h.2"/>
<path d="M170.4 191.8h.2M170.4 191.7h.2M170.4 191.6h.2M170.5 191.6h.1M170.6 191.5h.1M170.6 193h.4M170.8 192.8h.4M170.9 192.7h.3M170.9 192.6h.3M171 192.6h.2M171 192.5h.2M171 192.4h.2"/>
<path d="M171 192.3h.2M171 192.2h.2M171 192.1h.2M171 192h.2M171 191.9h.2M171 191.8h.2M171 191.7h.2M171 191.6h.2M171 192.9h-.9M171.1 191.5h.1M171.1 192.8h-1.1M171.4 192.7h.2"/>
<path d="M171.4 192.6h.2M171.4 192h.2M171.4 191.9h.2M171.4 192.7l.3 .1M171.4 192.1h.1M171.4 192.8h.6M171.4 191.8h.3M171.4 191.7h.9M171.5 192.9h.5M171.5 191.7h.8M171.5 191.7h.7M171.6 192l-.2 .1"/>
<path d="M171.6 191.6h.6M171.6 192h-.2M171.6 193h.4M171.6 192.3h.8M171.6 191.9h-.2M171.6 191.6h.5M171.6 192.5h-.2M171.7 192.5h-.3M171.7 192.2h.7M171.7 191.5h.3M171.7 191.8h-.3M171.8 192.4h-.4"/>
<path d="M171.8 192.2h.6M171.8 193h.1M171.9 193h.1M171.9 192.8h.1M171.9 192.4h-.5M171.9 192.1h.5M172 192.1h.4M172 192.3h-.5M172 191.8h.3M172.1 191.8h.2M172.1 191.9h.3M172.1 192h.3"/>
<path d="M172.1 192.8h.3M172.1 192.7h.3M172.1 192.6h.3M172.1 192.5h.3M172.1 192.4h.3M172.1 192.3h.3M172.3 193h-.2M172.3 192.9h-.2M172.4 192.9h-.3M172.4 192.3h-.9M172.7 192.9h.2M172.7 192.8h.2"/>
<path d="M172.7 192.7h.2M172.7 192.6h.2M172.7 192.5h.2M172.7 192.4h.2M172.7 192.3h.2M172.7 192.2h.2M172.7 192.1h.2M172.7 192h.2M172.7 191.9h.2M172.7 193h.1M172.7 191.9h.3M172.8 191.7h.8"/>
<path d="M172.8 193h-.1M172.8 191.7h.7M172.9 191.6h.6M172.9 192.9h-.2M172.9 192h-.2M172.9 191.6h.5M173 191.8l-.3 .1M173 191.5h.4M173.1 191.8h-.4M173.3 191.8h.4M173.4 191.8l.3 .1M173.4 191.9h.3"/>
<path d="M173.5 192h.2M173.5 191.9h.2M173.7 192l-.2 .1M173.7 192h-.2M174 192.6l.3 .1M174 192.6h.2M174 192.5h.2M174 192.2h.8M174 192.2h.2M174 192.1h.2M174 192h.2M174 191.9h.2"/>
<path d="M174 191.9h.3M174 192.7h.3M174.1 192.7l.4 .1M174.1 192.8h.8M174.1 191.7h.8M174.2 191.7h.7M174.2 192.9h.6M174.2 191.6h.6M174.3 193h.4M174.3 192.5h-.3M174.3 191.8l-.3 .1M174.3 191.5h.4"/>
<path d="M174.4 192.4h-.4M174.4 191.8h-.3M174.5 193h.1M174.5 191.7h-.4M174.5 192.4h-.5M174.5 191.7h.4M174.6 192.1h.4M174.6 192.3h-.6M174.6 191.8h.4M174.7 192.3h-.7M174.7 192h.3M174.7 191.8h.3"/>
<path d="M174.8 192.6h.2M174.8 191.9h.2M174.8 192h.2M174.8 192.5h.2M174.8 192.4h.2M174.9 192.8h-.8M174.9 192.2h-.6M174.9 192.7l-.3 .1M174.9 192.4h.1M175 192.7h-.3M175 192.2h-.6M175 192.1h-.5"/>
<path d="M180.5 192.5h.3M180.5 192.4h.3M180.5 192.3h.3M180.5 192.2h.3M180.5 192.1h.3M180.5 192h.3M180.5 191.9h.3M180.6 192.6h.3M180.6 192.5h.2M180.6 191.9h.2M180.6 191.8h.2M180.6 192.6l.4 .1"/>
<path d="M180.6 192.7h1M180.6 191.7h.9M180.6 192.7h.9M180.6 191.6h.9M180.7 192.8h.8M180.7 191.6h.8M180.7 192.9h.7M180.7 191.5h.7M180.8 191.5h.6M180.8 192.9h.5M180.9 193h.3M180.9 191.8h-.3"/>
<path d="M180.9 191.4h.3M181 191.7h-.4M181.2 191.7h.4M181.2 192.7h.4M181.2 192.6h.4M181.2 191.8h.4M181.3 192.6h.3M181.3 191.8l.3 .1M181.3 192.5h.3M181.3 192.4h.3M181.3 192.3h.3M181.3 192.2h.3"/>
<path d="M181.3 192.1h.3M181.3 192h.3M181.3 191.9h.3M181.6 192.5h-.3M181.9 193.3h.3M181.9 193.2h.3M181.9 193.1h.3M181.9 193h.3M181.9 192.7h1M181.9 192.7h1.1M181.9 192.6l.5 .1M181.9 192.6h.4"/>
<path d="M181.9 192.5h.3M181.9 192.4h.3M181.9 192.3h.3M181.9 192.2h.3M181.9 192.1h.3M181.9 192h.3M181.9 191.9h.3M181.9 193.5h.2M182 191.7h1M182 191.7h.9M182 191.6h.9M182.1 191.6h.8"/>
<path d="M182.1 191.5h.7M182.2 193.4h-.3M182.2 191.5h.6M182.3 191.8l-.4 .1M182.3 193h.3M182.3 191.8h-.4M182.3 191.4h.3M182.4 191.7h-.4M182.6 191.7h.4M182.6 192.7h.4M182.6 191.8h.4M182.6 192.6h.4"/>
<path d="M182.7 192.6h.3M182.7 192.5h.3M182.7 191.8l.3 .1M182.7 191.9h.3M182.7 192.9h-.8M182.7 192.4h.3M182.7 192.3h.3M182.7 192.2h.3M182.7 192.1h.3M182.7 192h.3M182.8 192.9h-.9M182.8 192.8h-.9"/>
<path d="M182.9 192.8h-1M183.2 197.1v2.8M183.3 192.6l.5 .1M183.3 192.6h.4M183.3 192.5h.3M183.3 192.1h1.1M183.3 192l.3 .1M183.3 192h.3M183.3 191.8h.4M183.4 192.7h.9M183.4 191.7h.9M183.4 191.6h.9"/>
<path d="M183.5 192.8h.8M183.5 191.6h.8M183.5 192.8h.7M183.5 191.5h.7M183.5 192.9h.7M183.6 191.5h.5M183.6 192.9h.5M183.6 191.9h-.3M183.7 192.4h-.4M183.7 192.1h.7M183.7 191.8h-.4M183.7 193h.3"/>
<path d="M183.7 191.4h.3M183.8 191.7h-.4M183.8 192.4h-.5M183.9 192h.5M183.9 192.3h-.6M184 192h.4M184 191.7h.4M184 192.3h-.7M184 191.8h.4M184.1 192.6h.3M184.1 191.9h.3M184.1 191.8h.3"/>
<path d="M184.1 192.5h.3M184.1 192.4h.3M184.1 192.2l-.8 .1M184.2 192.3h.2M184.2 192.2h-.9M184.3 192.2h-1M184.3 192.3h.1M184.4 192.6l-.4 .1M184.4 192.6h-.4M184.7 192.9h.2M184.7 192.8h.3M184.7 192.7h.3"/>
<path d="M184.7 192.6h.3M184.7 192.5h.3M184.7 192.4h.3M184.7 192.3h.3M184.7 192.2h.3M184.7 192.1h.3M184.7 192h.3M184.7 191.9h.3M184.8 193h.1M184.8 191.7h.9M184.8 191.6h.9M184.9 191.6h.8"/>
<path d="M184.9 191.5h.7M185 191.5h.5M185 192.9h-.3M185 191.9h-.3M185.1 191.8l-.4 .1M185.1 191.8h-.4M185.1 191.4h.3M185.2 191.7h-.4M185.4 191.7h.4M185.4 191.8h.4M185.5 191.8l.3 .1M185.5 192.9h.2"/>
<path d="M185.5 192.8h.3M185.5 192.7h.3M185.5 192.6h.3M185.5 192.5h.3M185.5 192.4h.3M185.5 192.3h.3M185.5 192.2h.3M185.5 192.1h.3M185.5 192h.3M185.5 191.9h.3M185.5 193h.1M185.7 191.7h-.9"/>
<path d="M185.8 192.9h-.3M187 192.9h.2M187 192.8h.2M187 192.7h.2M187 192.6h.2M187 192.5h.2M187 192.4h.2M187 192.3h.2M187 192.2h.2M187 192.1h.2M187 192h.2M187 191.9h.2"/>
<path d="M187 191.7h.9M187 191.6l.9 .1M187 191.6h.8M187 191.6h.7M187 191.5h.2M187 191.4h.2M187 191.3h.2M187 191.2h.2M187 191.1h.2M187.1 191h.1M187.1 193h-.1M187.2 192.9h-.2"/>
<path d="M187.3 191.8l-.3 .1M187.3 191.5h.4M187.4 191.8h-.4M187.5 191.7h-.5M187.5 191.7h.4M187.6 191.8h.4M187.7 191.8l.3 .1M187.7 191.9h.3M187.8 191.9h.2M187.8 193h.1M187.8 192.9h.2M187.8 192.8h.2"/>
<path d="M187.8 192.7h.2M187.8 192.6h.2M187.8 192.5h.2M187.8 192.4h.2M187.8 192.3h.2M187.8 192.2h.2M187.8 192.1h.2M187.8 192h.2M188 192.9h-.2M188.3 192.6h.3M188.3 192.6h.2M188.3 192h.2"/>
<path d="M188.3 192.7l.4 .1M188.3 192.7h.3M188.3 192.5h.3M188.3 192.1h.1M188.3 191.9h.3M188.4 192.8h.6M188.4 192.9h.6M188.4 191.7h.8M188.5 191.7h.7M188.5 192.9h.5M188.5 192l-.2 .1M188.5 191.6h.6"/>
<path d="M188.5 192h-.2M188.6 192.6h-.3M188.6 192.3h.7M188.6 191.9h-.3M188.6 193h.4M188.6 192.5h-.3M188.6 191.6h.5M188.6 191.8l-.2 .1M188.7 192.2h.6M188.7 191.5h.3M188.7 191.8h-.3M188.7 192.4h-.4"/>
<path d="M188.7 193h.1M188.8 192.8h.1M188.9 192.4h-.5M188.9 192.1h.4M189 192.3h-.6M189 191.8h.3M189.1 192h.2M189.1 191.9h.2M189.1 192.8h.2M189.1 192.7h.2M189.1 192.6h.2M189.1 192.5h.2"/>
<path d="M189.1 192.4h.2M189.1 192.3h.2M189.2 193h-.1M189.3 191.7h-.9M189.3 192.9h-.2M189.3 192.3h-.8M189.7 192.9h.2M189.7 192.8h.2M189.7 192.7h.2M189.7 192.6h.2M189.7 192.5h.2M189.7 192.4h.2"/>
<path d="M189.7 192.3h.2M189.7 192.2h.2M189.7 192.1h.2M189.7 192h.2M189.7 191.9h.2M189.7 191.7h.8M189.8 193h-.1M189.8 191.7h.7M189.8 191.6h.7M189.8 192.9h-.1M189.9 191.6h.5M189.9 191.8l-.2 .1"/>
<path d="M190 191.5h.3M190 191.8h-.3M190.3 191.8h.3M190.4 191.8l.2 .1M190.4 191.9h.2M190.4 192h.2M190.6 191.7h-.9M190.6 192l-.1 .1M190.6 192h-.2M191 192.6h.2M191 192.5h.2M191 192.4h.2"/>
<path d="M191 192.3h.2M191 192.2h.2M191 192.1h.2M191 192h.2M191 191.9h.2M191 192.6l.2 .1M191 192.7h.3M191 192.7l.4 .1M191.1 192.8h.8M191.1 191.7h.9M191.1 192.9h.7M191.1 191.6h.9"/>
<path d="M191.2 191.6h.8M191.2 192.9h.6M191.2 191.9h-.2M191.3 193h.4M191.3 191.8l-.3 .1M191.3 191.5h.3M191.3 191.8h-.3M191.4 191.7h-.3M191.4 193h.1M191.5 193h.1M191.5 191.7h.5M191.6 191.8h.4"/>
<path d="M191.7 191.8h.3M191.7 192.7h.2M191.7 191.9h.3M191.7 192.6h.3M191.7 192.5h.3M191.7 192.4h.3M191.7 192.3h.3M191.7 192.2h.3M191.7 192.1h.3M191.7 192h.3M191.7 191.5h.3M191.7 191.4h.3"/>
<path d="M191.7 191.3h.3M191.7 191.2h.3M191.7 191.1h.3M191.8 191.1h.2M191.9 191h.1M191.9 192.7l-.4 .1M191.9 192.7h-.3M192 192.6h-.3M192.2 192.7l.3 .1M192.2 192.7h.2M192.2 192.6l.2 .1M192.2 192.6h.2"/>
<path d="M192.2 192.5h.2M192.2 192.4h.2M192.2 192.3h.2M192.2 192.2h.2M192.2 192.1h.2M192.2 192h.2M192.2 191.9h.2M192.2 191.8h.2M192.2 191.7h.2M192.2 191.6h.2M192.2 192.8h1.2M192.2 192.9h1.1"/>
<path d="M192.3 192.9h1M192.3 191.5h.1M192.3 193h.4M192.6 192.8h.4M192.6 193h.1M192.6 192.7h.3M192.7 192.6h.2M192.7 192.5h.2M192.7 192.4h.2M192.7 192.3h.2M192.7 192.2h.2M192.7 192.1h.2"/>
<path d="M192.7 192h.2M192.7 191.9h.2M192.7 191.8h.2M192.7 191.7h.2M192.7 191.6h.2M192.8 193h.4M192.8 191.5h.1M193.1 192.8h.3M193.2 192.7h.2M193.2 192.6h.2M193.2 192.5h.2M193.2 192.4h.2"/>
<path d="M193.2 192.3h.2M193.2 192.2h.2M193.2 192.1h.2M193.2 192h.2M193.2 191.9h.2M193.2 191.8h.2M193.2 191.7h.2M193.2 191.6h.2M193.3 191.6h.1M193.3 191.5h.1M193.4 192.8h-1.2M193.6 192.7h.3"/>
<path d="M193.6 192.6h.2M193.6 192h.2M193.6 191.9h.2M193.6 192.7l.4 .1M193.6 192.1h.1M193.7 192.8h.5M193.7 191.8h.2M193.7 192.8h.6M193.7 191.7h.8M193.7 192.9h.6M193.8 191.7h.7M193.8 192.9h.5"/>
<path d="M193.8 192l-.2 .1M193.8 191.6h.6M193.8 192h-.2M193.8 193h.5M193.8 192.3h.8M193.9 191.9h-.3M193.9 191.6h.5M193.9 192.5h-.3M193.9 192.2h.7M194 191.5h.3M194 191.8h-.3M194 192.4h-.3"/>
<path d="M194 192.2h.6M194.1 193h.1M194.1 192.8h.1M194.2 192.4h-.5M194.2 192.1h.4M194.2 192.3h-.5M194.2 191.8h.4M194.3 191.8h.3M194.4 191.9h.2M194.4 192h.2M194.4 192.8h.2M194.4 192.7h.2"/>
<path d="M194.4 192.6h.2M194.4 192.5h.2M194.4 192.4h.2M194.4 192.3h.2M194.5 193h-.1M194.6 192.9h-.2M194.6 192.3h-.8M194.9 192.9h.2M194.9 192.8h.2M194.9 192.7h.2M194.9 192.6h.2M194.9 192.5h.2"/>
<path d="M194.9 192.4h.2M194.9 192.3h.2M194.9 192.2h.2M194.9 192.1h.2M194.9 192h.2M194.9 191.9h.3M195 191.9h.2M195 193h.1M195 191.7h.9M195 191.7h.8M195.1 193h-.2M195.1 191.7h.7"/>
<path d="M195.1 191.6h.6M195.1 192.9h-.2M195.2 192h-.3M195.2 191.6h.5M195.2 191.8l-.2 .1M195.3 191.5h.3M195.3 191.8h-.3M195.6 191.8h.3M195.6 191.8l.3 .1M195.7 191.9h.2M195.7 192h.2M195.9 192l-.2 .1"/>
<path d="M195.9 192h-.2M196.3 192.6h.2M196.3 192.5h.2M196.3 192.2h.8M196.3 192.2h.2M196.3 192.1h.2M196.3 192h.2M196.3 191.9h.2M196.3 192.7h.3M196.3 192.6l.2 .1M196.3 192.7l.4 .1M196.3 192.8h.9"/>
<path d="M196.4 191.7h.8M196.4 191.7h.7M196.4 192.9h.7M196.4 191.6h.7M196.5 192.9h.5M196.5 191.6h.5M196.5 193h.5M196.5 192.5h-.2M196.6 191.8l-.3 .1M196.6 191.5h.3M196.6 192.4h-.3M196.6 191.8h-.3"/>
<path d="M196.7 191.7h-.4M196.7 193h.1M196.8 192.1h.5M196.8 192.4h-.5M196.8 191.7h.4M196.8 192.3h-.5M196.9 191.8h.3M197 192.3h-.7M197 192h.3M197 191.8l.3 .1M197 192.6h.2M197 191.9h.3"/>
<path d="M197 192.6h.3M197.1 192.5h.2M197.1 192.4h.2M197.1 192.8h-.7M197.2 192.2h-.6M197.2 192.7l-.4 .1M197.2 192.4h.1M197.2 192.7h-.3M197.2 192.2h-.5M217.9 197.1v2.8M252.5 197.1v2.8M287.2 197h.1"/>
<circle cx="14.6" cy="179.5" r="1.48"/>
<circle cx="14.6" cy="179.5" r=".38"/>
<circle cx="42.4" cy="179.5" r="1.48"/>
<circle cx="42.4" cy="179.5" r=".38"/>
<circle cx="14.6" cy="190.6" r="1.48"/>
<circle cx="14.6" cy="190.6" r=".38"/>
<circle cx="42.4" cy="190.6" r="1.48"/>
<circle cx="42.4" cy="190.6" r=".38"/>
</g>
<path d="M149 60.8h3.8v61.2h-3.8zM188 60.8h3.7v61.2h-3.7zM226.9 60.8h3.7v61.2h-3.7zM83.2 87.4h5.6v8.1h-5.6zM42.4 107.7h5.6v8.2h-5.6zM42.4 117h5.6v8.2h-5.6z" fill="none" stroke="#000" stroke-width=".32"/>
<g fill="none" stroke="#000" stroke-width=".47">
<path d="M10 12.6h277.2v184.5h-277.2zM150 79.4h.9M150 77.5h.9M150 75.7h.9M150 73.8h.9M150 72h.9M150 70.1h.9M150 68.3h.9M150 66.4h.9M150 64.6h.9M150 62.7h.9M188.9 79.4h.9"/>
<path d="M188.9 77.5h.9M188.9 75.7h.9M188.9 73.8h.9M188.9 72h.9M188.9 70.1h.9M188.9 68.3h.9M188.9 66.4h.9M188.9 64.6h.9M188.9 62.7h.9M227.8 79.4h1M227.8 77.5h1M227.8 75.7h1"/>
<path d="M227.8 73.8h1M227.8 72h1M227.8 70.1h1M227.8 68.3h1M227.8 66.4h1M227.8 64.6h1M227.8 62.7h1M150 99.8h.9M150 97.9h.9M150 96.1h.9M150 94.2h.9M150 92.4h.9"/>
<path d="M150 90.5h.9M150 88.6h.9M150 86.8h.9M150 84.9h.9M150 83.1h.9M150 81.2h.9M188.9 99.8h.9M188.9 97.9h.9M188.9 96.1h.9M188.9 94.2h.9M188.9 92.4h.9M188.9 90.5h.9"/>
<path d="M188.9 88.6h.9M188.9 86.8h.9M188.9 84.9h.9M188.9 83.1h.9M188.9 81.2h.9M227.8 99.8h1M227.8 97.9h1M227.8 96.1h1M227.8 94.2h1M227.8 92.4h1M227.8 90.5h1M227.8 88.6h1"/>
<path d="M227.8 86.8h1M227.8 84.9h1M227.8 83.1h1M227.8 81.2h1M150 118.3h.9M150 116.5h.9M150 114.6h.9M150 112.8h.9M150 110.9h.9M150 109h.9M150 107.2h.9M150 105.3h.9"/>
<path d="M150 103.5h.9M150 101.6h.9M188.9 118.3h.9M188.9 116.5h.9M188.9 114.6h.9M188.9 112.8h.9M188.9 110.9h.9M188.9 109h.9M188.9 107.2h.9M188.9 105.3h.9M188.9 103.5h.9M188.9 101.6h.9"/>
<path d="M227.8 118.3h1M227.8 116.5h1M227.8 114.6h1M227.8 112.8h1M227.8 110.9h1M227.8 109h1M227.8 107.2h1M227.8 105.3h1M227.8 103.5h1M227.8 101.6h1M150 120.2h.9M188.9 120.2h.9"/>
<path d="M227.8 120.2h1M224.1 174.9v22.2M287.2 174.9h-85.3v22.2"/>
</g>
<g fill="none" stroke="#000" stroke-width=".19">
<path d="M42.4 99.1h3.7v1.3h-3.7zM83.2 82.4h3.7v1.3h-3.7zM83.2 80.6h3.7v1.3h-3.7zM84.2 88.1h3.7v1.1h-3.7zM84.2 89.9h3.7v1.2h-3.7zM84.2 91.8h3.7v1.1h-3.7zM84.2 93.7h3.7v1.1h-3.7zM42.4 101h3.7v1.3h-3.7zM42.4 102.8h3.7v1.3h-3.7zM42.4 104.7h3.7v1.3h-3.7zM43.4 108.5h3.7v1.1h-3.7zM43.4 110.3h3.7v1.1h-3.7z"/>
<path d="M43.4 112.2h3.7v1.1h-3.7zM43.4 114h3.7v1.2h-3.7zM43.4 117.8h3.7v1.1h-3.7zM43.4 119.6h3.7v1.1h-3.7zM42.4 128.8h3.7v1.3h-3.7zM42.4 130.6h3.7v1.3h-3.7zM42.4 132.5h3.7v1.3h-3.7zM43.4 121.5h3.7v1.1h-3.7zM43.4 123.3h3.7v1.1h-3.7zM112 138.2l.9-1.4 .9 1.4M119.4 138.2l.9-1.4 .9 1.4M263.5 127.6h2.8"/>
<path d="M111.5 149.8h2.8M111.8 142.4h2.2v.7h-2.2zM118.9 149.8h2.8M119.2 142.4h2.2v.7h-2.2zM224.1 178.6h63.1M224.1 182.3h63.1M224.1 186h63.1M224.1 189.7h63.1M266.8 186v3.7M287.2 192.5v.9h-63.1"/>
</g>
<path d="M7.2 9.9h282.7v190h-282.7z" fill="none" stroke="#000" stroke-width=".23"/>
<g fill="#000" stroke="#000" stroke-width=".18">
<path d="M33.2 56.9h2v.4h-2zM33.2 58.8h2v.4h-2zM74 56.9h2v.4h-2zM74 58.8h2v.4h-2zM33.2 60.6h2v.4h-2zM33.2 62.5h2v.4h-2zM33.2 64.4h2v.3h-2zM33.2 66.2h2v.4h-2zM33.2 68.1h2v.4h-2zM33.2 69.9h2v.4h-2zM33.2 71.8h2v.4h-2zM33.2 73.6h2v.4h-2z"/>
<path d="M33.2 75.5h2v.4h-2zM33.2 77.3h2v.4h-2zM33.2 79.2h2v.4h-2zM74 60.6h2v.4h-2zM74 62.5h2v.4h-2zM74 64.4h2v.3h-2zM74 66.2h2v.4h-2zM74 68.1h2v.4h-2zM74 69.9h2v.4h-2zM74 71.8h2v.4h-2zM74 73.6h2v.4h-2zM74 75.5h2v.4h-2z"/>
<path d="M74 77.3h2v.4h-2zM268.4 60.6h2.1v.4h-2.1zM268.4 62.5h2.1v.4h-2.1zM268.4 64.4h2.1v.3h-2.1zM268.4 66.2h2.1v.4h-2.1zM268.4 68.1h2.1v.4h-2.1zM268.4 69.9h2.1v.4h-2.1zM268.4 71.8h2.1v.4h-2.1zM268.4 73.6h2.1v.4h-2.1zM33.2 81h2v.4h-2zM33.2 82.9h2v.4h-2zM33.2 84.8h2v.3h-2z"/>
<path d="M33.2 86.6h2v.4h-2zM33.2 88.5h2v.3h-2zM33.2 90.3h2v.4h-2zM33.2 92.2h2v.3h-2zM33.2 94h2v.4h-2zM33.2 95.9h2v.3h-2zM33.2 99.6h2v.4h-2zM74 81h2v.4h-2zM74 82.9h2v.4h-2zM74 88.5h2v.3h-2zM74 90.3h2v.4h-2zM74 92.2h2v.3h-2z"/>
<path d="M74 94h2v.4h-2zM268.4 81h2.1v.4h-2.1zM268.4 82.9h2.1v.4h-2.1zM268.4 84.8h2.1v.3h-2.1zM268.4 86.6h2.1v.4h-2.1zM268.4 88.5h2.1v.3h-2.1zM268.4 90.3h2.1v.4h-2.1zM268.4 92.2h2.1v.3h-2.1zM268.4 94h2.1v.4h-2.1zM268.4 95.9h2.1v.3h-2.1zM268.4 97.7h2.1v.4h-2.1zM268.4 99.6h2.1v.4h-2.1z"/>
<path d="M33.2 101.4h2v.4h-2zM33.2 103.3h2v.4h-2zM33.2 105.1h2v.4h-2zM33.2 108.8h2v.4h-2zM33.2 110.7h2v.4h-2zM33.2 112.6h2v.3h-2zM33.2 114.4h2v.4h-2zM33.2 118.1h2v.4h-2zM33.2 120h2v.4h-2zM74 101.4h2v.4h-2zM74 103.3h2v.4h-2zM74 105.1h2v.4h-2z"/>
<path d="M74 107h2v.4h-2zM74 108.8h2v.4h-2zM74 110.7h2v.4h-2zM74 112.6h2v.3h-2zM74 114.4h2v.4h-2zM74 116.3h2v.3h-2zM74 118.1h2v.4h-2zM74 120h2v.4h-2zM268.4 101.4h2.1v.4h-2.1zM268.4 103.3h2.1v.4h-2.1zM268.4 105.1h2.1v.4h-2.1zM268.4 107h2.1v.4h-2.1z"/>
<path d="M268.4 108.8h2.1v.4h-2.1zM268.4 110.7h2.1v.4h-2.1zM268.4 112.6h2.1v.3h-2.1zM268.4 114.4h2.1v.4h-2.1zM268.4 116.3h2.1v.3h-2.1zM268.4 118.1h2.1v.4h-2.1zM268.4 120h2.1v.4h-2.1zM33.2 121.8h2v.4h-2zM33.2 123.7h2v.4h-2zM33.2 129.2h2v.4h-2zM33.2 131.1h2v.4h-2zM33.2 132.9h2v.4h-2z"/>
<path d="M33.2 134.8h2v.4h-2zM74 121.8h2v.4h-2zM74 123.7h2v.4h-2zM74 125.5h2v.4h-2zM74 127.4h2v.4h-2zM74 129.2h2v.4h-2zM74 131.1h2v.4h-2zM74 132.9h2v.4h-2zM74 134.8h2v.4h-2zM74 136.7h2v.3h-2zM74 138.5h2v.4h-2zM268.4 121.8h2.1v.4h-2.1z"/>
<path d="M268.4 123.7h2.1v.4h-2.1zM33.2 140.4h2v.3h-2zM33.2 142.2h2v.4h-2zM74 140.4h2v.3h-2zM111.7 143.6h2.4v.7h-2.4zM119.1 143.6h2.4v.7h-2.4z"/>
</g>
<g fill="none" stroke="#000" stroke-width=".3">
<path d="M162.5 187.3h2.9M162.5 187.1h2.9M162.5 186.8h2.9M162.5 186.6h2.9M163.1 186.3h2.4M163.4 184.4h1.6M163.4 189.5h1.5M163.5 189.3h2.2M163.6 184.6h6.1M163.6 184.1h1.1M163.7 189.8h.9M163.7 189h2.1"/>
<path d="M163.8 184.8h5.7M163.8 183.9h.6M163.9 187.6h1.6M163.9 188.8h2M163.9 186.1h1.8M163.9 190h.4M163.9 187.8h1.8M164 185.8h1.9M164 185.1h5.3M164 188h2.1M164.1 183.6l1 .9 .9-.4M164.1 183.6l-.7 .7 .8 1.1-.3 .8-1.4 .2v1l1.4 .1 .1 .4"/>
<path d="M164.1 183.6h.1M164.1 185.6h5.1M164.1 188.6h1.9M164.2 188.3h1.9M164.2 185.3h4.9M165.3 184.4h2.7M165.5 189.5h.1M166 184.1h1.3M166 184.1l.2-1.3h1l.1 1.3M166 183.9h1.3M166.1 183.6h1.2M166.1 183.4h1.1"/>
<path d="M166.1 183.1h1.1M166.1 182.9h1.1M166.6 185.6a1.3 1.3 0 0 0-1.2 1.1 1.3 1.3 0 0 0 .8 1.4l-.6 1.4-.5-.2-1 .9-.7-.7 .8-1.1-.2-.5M166.8 185.6l.6 .2M167.2 188.3h2M167.3 188h2M167.3 188.6h1.9M167.4 185.8a1.31 1.31 0 0 1-.2 2.3l.5 1.4 .5-.2 1 .9 .7-.7-.8-1.1 .3-.5M167.4 185.8h1.9M167.4 188.8h2M167.5 189h2.1M167.6 187.8h1.8"/>
<path d="M167.6 189.3h2.2M167.7 186.1h1.7M167.7 189.5h.1M167.8 187.6h1.6M167.8 186.3h2.4M167.9 187.3h2.9M167.9 186.6h2.9M167.9 187.1h2.9M168 186.8h2.8M168.3 184.4h1.6M168.4 189.5h1.5M168.6 184.1h1.1"/>
<path d="M168.7 189.8h.9M168.9 183.9h.6M169 190h.4M169.2 183.6l.7 .7-.8 1.1 .4 .8 1.3 .2v1l-1.3 .1-.1 .4M169.2 183.6l-1 .9-.9-.4M169.2 183.6h.1M184.8 187.3h2.9M184.8 187.1h2.8M184.8 186.8h2.8M184.8 186.6h2.8M185.4 186.3h2.3M185.6 184.4h1.6"/>
<path d="M185.7 189.5h1.4M185.8 189.3h2.1M185.8 184.6h6.2M185.8 184.1h1.1M185.9 189.8h.9M186 189h2M186 184.8h5.8M186.1 183.9h.5M186.1 187.6h1.7M186.2 188.8h1.9M186.2 186.1h1.7M186.2 190h.3"/>
<path d="M186.2 187.8h1.8M186.2 185.8h2M186.2 185.1h5.4M186.3 188h2M186.3 183.6h.1M186.3 183.6l1.1 .9 .9-.4M186.3 183.6l-.7 .7 .9 1.1-.4 .8-1.3 .2v1l1.3 .1 .1 .4M186.4 185.6h5.1M186.4 188.6h1.8M186.4 188.3h1.9M186.4 185.3h5M187.6 184.4h2.6"/>
<path d="M187.8 189.5h.1M188.2 184.1h1.4M188.3 184.1l.1-1.3h1l.1 1.3M188.3 183.9h1.2M188.3 183.6h1.2M188.3 183.4h1.2M188.4 183.1h1M188.4 182.9h1M188.8 185.6a1.3 1.3 0 0 0-1.2 1.1 1.3 1.3 0 0 0 .8 1.4l-.6 1.4-.4-.2-1.1 .9-.7-.7 .9-1.1-.3-.5M189 185.6l.6 .2M189.5 188.3h1.9M189.5 188h2"/>
<path d="M189.6 188.6h1.8M189.6 185.8a1.31 1.31 0 0 1-.2 2.3l.6 1.4 .4-.2 1.1 .9 .7-.7-.9-1.1 .3-.5M189.7 185.8h1.9M189.7 188.8h1.9M189.8 189h2M189.8 187.8h1.8M189.9 189.3h2.1M189.9 186.1h1.7M190 189.5h.1M190 187.6h1.7M190.1 186.3h2.3M190.1 187.3h2.9"/>
<path d="M190.2 186.6h2.8M190.2 187.1h2.8M190.2 186.8h2.8M190.6 184.4h1.6M190.7 189.5h1.4M190.9 184.1h1.1M191 189.8h.9M191.2 183.9h.5M191.3 190h.3M191.5 183.6h.1M191.5 183.6l.7 .7-.9 1.1 .4 .8 1.3 .2v1l-1.3 .1-.1 .4M191.5 183.6l-1.1 .9-.9-.4"/>
</g>
<g fill="#000" stroke="#000" stroke-width=".18">
<path d="M13.1 179.5h1.2l.1 .2 .2 .2v1.1a1.48 1.48 0 0 1-1.5-1.5z" fill-rule="evenodd"/>
<path d="M14.6 178a1.45 1.45 0 0 1 1.5 1.5h-1.1l-.1-.3-.3-.1z" fill-rule="evenodd"/>
<path d="M41.4 178.4l.6-.3 .4-.1v1.1l-.2 .1-.1 .3h-1.1v-.5z" fill-rule="evenodd"/>
<path d="M42.4 179.9l.3-.2 .1-.2h1.1a1.48 1.48 0 0 1-1.5 1.5z" fill-rule="evenodd"/>
<path d="M13.1 190.6h1.2l.1 .3 .2 .1v1.1a1.45 1.45 0 0 1-1.5-1.5z" fill-rule="evenodd"/>
<path d="M14.6 189.1a1.45 1.45 0 0 1 1.5 1.5h-1.1l-.1-.2-.3-.2z" fill-rule="evenodd"/>
<path d="M41.4 189.5l.6-.3 .4-.1v1.1l-.2 .2-.1 .2h-1.1v-.5z" fill-rule="evenodd"/>
<path d="M42.4 191l.3-.1 .1-.3h1.1a1.45 1.45 0 0 1-1.5 1.5z" fill-rule="evenodd"/>
<circle cx="264.9" cy="64.6" r=".38"/>
<circle cx="264.9" cy="73.8" r=".38"/>
<circle cx="264.9" cy="68.3" r=".38"/>
<circle cx="264.9" cy="70.1" r=".38"/>
<circle cx="264.9" cy="66.4" r=".38"/>
<circle cx="264.9" cy="72" r=".38"/>
<circle cx="264.9" cy="62.7" r=".38"/>
<circle cx="264.9" cy="81.2" r=".38"/>
<circle cx="264.9" cy="84.9" r=".38"/>
<circle cx="264.9" cy="83.1" r=".38"/>
<circle cx="264.9" cy="86.8" r=".38"/>
<circle cx="264.9" cy="94.2" r=".38"/>
<circle cx="264.9" cy="97.9" r=".38"/>
<circle cx="264.9" cy="99.8" r=".38"/>
<circle cx="264.9" cy="92.4" r=".38"/>
<circle cx="264.9" cy="88.6" r=".38"/>
<circle cx="264.9" cy="90.5" r=".38"/>
<circle cx="264.9" cy="96.1" r=".38"/>
<circle cx="264.9" cy="103.5" r=".38"/>
<circle cx="264.9" cy="116.5" r=".38"/>
<circle cx="264.9" cy="110.9" r=".38"/>
<circle cx="264.9" cy="109" r=".38"/>
<circle cx="264.9" cy="107.2" r=".38"/>
<circle cx="264.9" cy="105.3" r=".38"/>
<circle cx="264.9" cy="101.6" r=".38"/>
<circle cx="264.9" cy="114.6" r=".38"/>
<circle cx="264.9" cy="112.8" r=".38"/>
<circle cx="264.9" cy="118.3" r=".38"/>
<circle cx="264.9" cy="123.9" r=".38"/>
<circle cx="264.9" cy="122" r=".38"/>
<circle cx="264.9" cy="120.2" r=".38"/>
</g>
<path d="M103.6 99.8h-3.7l-1.8 1.8v29.7" fill="none" stroke="#000" stroke-width=".57"/>
<use href="#words"/>
</svg>
